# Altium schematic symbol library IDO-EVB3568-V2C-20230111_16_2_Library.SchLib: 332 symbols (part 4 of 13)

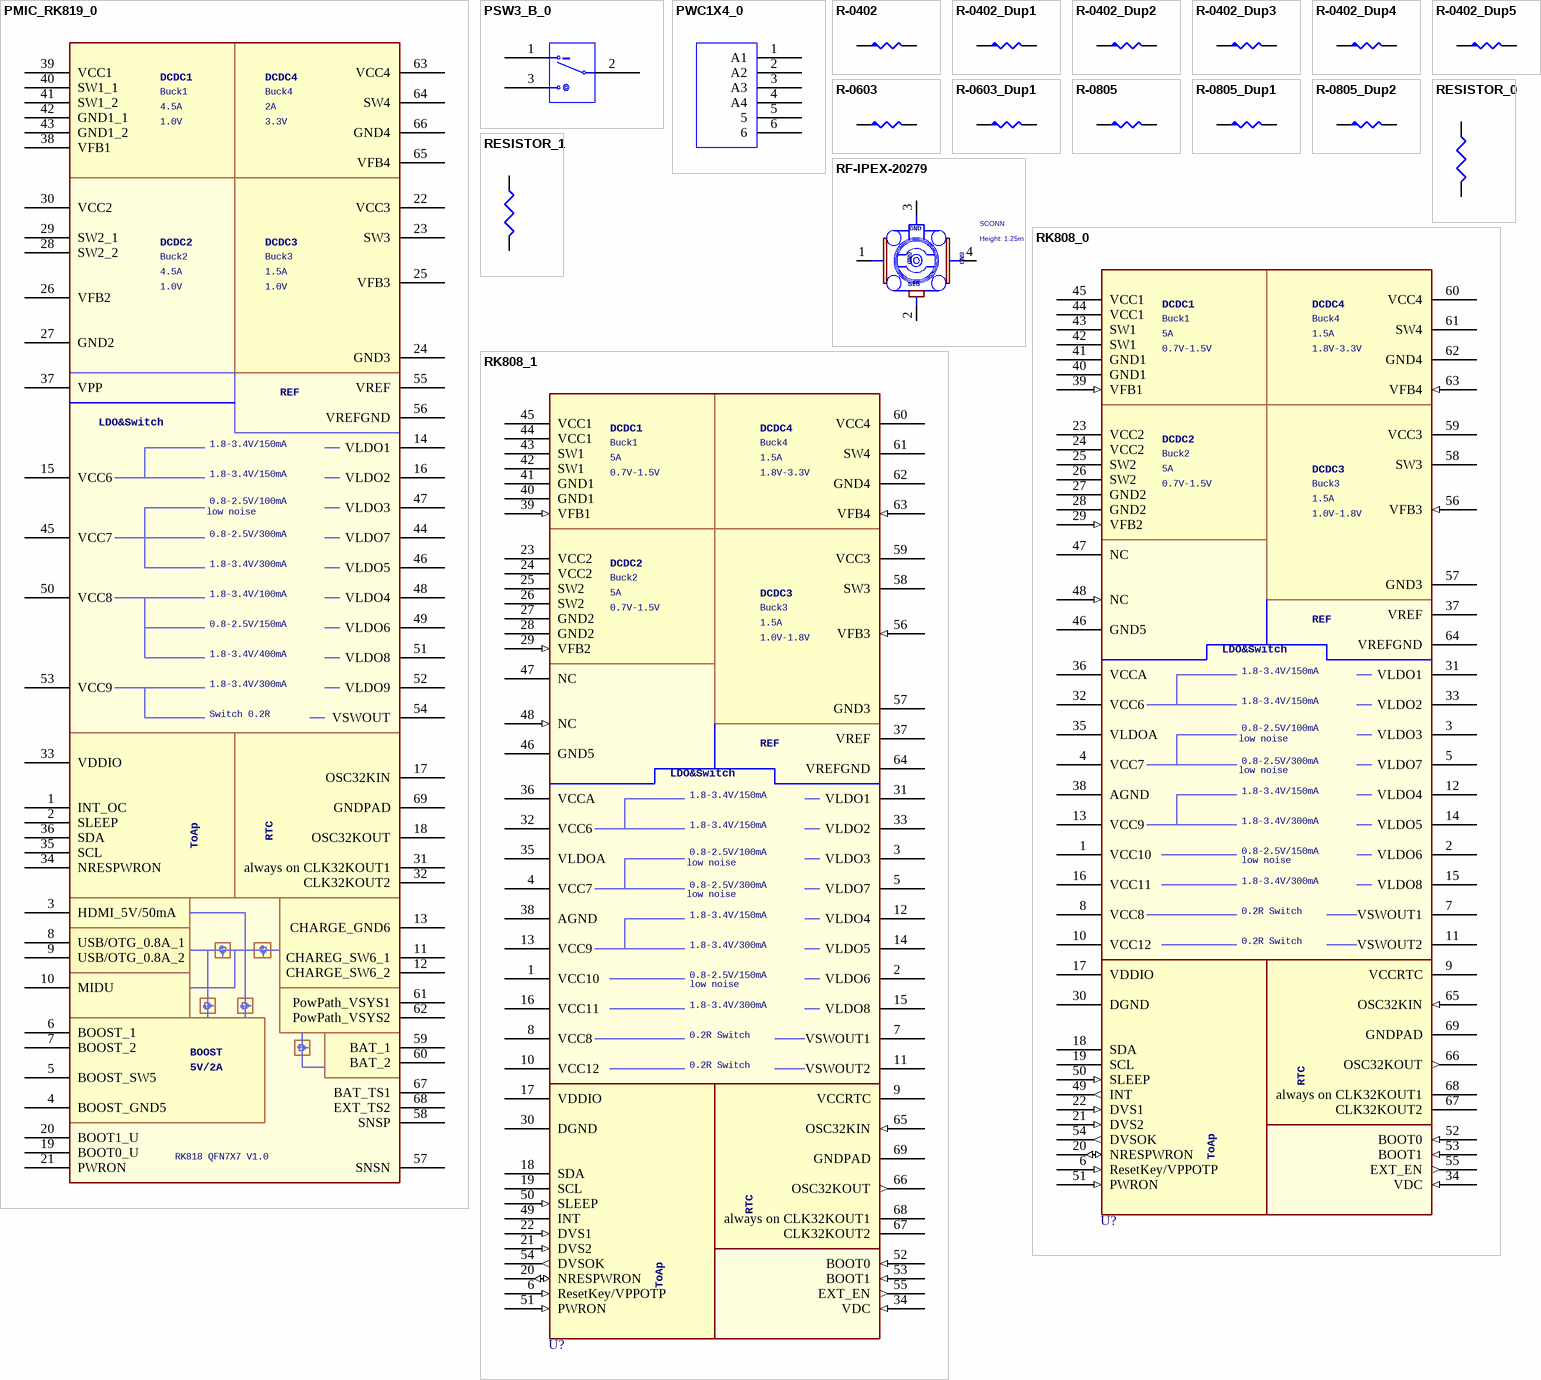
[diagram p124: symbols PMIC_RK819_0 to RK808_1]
## PWC1X4_0
designator J?, comment PWC1X4  (value not drawn)
PARTS: 1; DEVICE: HEAD1X4; LEVEL: STD; PKG_TYPE: 4; OriginalSymbolOrigin: (0,70)
pins: 1 A1, 2 A2, 3 A3, 4 A4, 5, 6

## R-0402
designator R?
pins: 1, 2

## R-0402_Dup1
designator R?
pins: 1, 2

## R-0402_Dup2
designator R?
pins: 1, 2

## R-0402_Dup3
designator R?
pins: 1, 2

## R-0402_Dup4
designator R?
pins: 1, 2

## R-0402_Dup5
designator R?
pins: 1, 2

## R-0603
designator R?
pins: 1, 2

## R-0603_Dup1
designator R?
pins: 1, 2

## R-0805
designator R?
pins: 1, 2

## R-0805_Dup1
designator R?
pins: 1, 2

## R-0805_Dup2
designator R?
pins: 1, 2

## RESISTOR_0
designator R?
pins: 1, 2

## RESISTOR_1
designator R?
pins: 1, 2

## RF-IPEX-20279
designator IPEX?  Material: SCONN  Height: 1.25mm
SMD micro Coaxial Connector Receptacle vertial; Pack_Type: MHF-20279
pins: 1 GND1, 2 SIG, 3 GND2, 4 GND3

## RK808_0
designator U?  (value not drawn)
pins: 1 VCC10 (power), 2 VLDO6 (power), 3 VLDO3 (power), 4 VCC7 (power), 5 VLDO7 (power), 6 ResetKey/VPPOTP (in), 7 VSWOUT1 (power), 8 VCC8 (power), 9 VCCRTC (power), 10 VCC12 (power), 11 VSWOUT2 (power), 12 VLDO4 (power), 13 VCC9 (power), 14 VLDO5 (power), 15 VLDO8 (power), 16 VCC11 (power), 17 VDDIO (power), 18 SDA (oc), 19 SCL (oc), 20 NRESPWRON (io), 21 DVS2 (in), 22 DVS1 (in), 23 VCC2 (power), 24 VCC2 (power), 25 SW2 (power), 26 SW2 (power), 27 GND2 (power), 28 GND2 (power), 29 VFB2 (in), 30 DGND (power), 31 VLDO1 (power), 32 VCC6 (power), 33 VLDO2 (power), 34 VDC (in), 35 VLDOA (power), 36 VCCA (power), 37 VREF (power), 38 AGND (power), 39 VFB1 (in), 40 GND1 (power), 41 GND1 (power), 42 SW1 (power), 43 SW1 (power), 44 VCC1 (power), 45 VCC1 (power), 46 GND5 (power), 47 NC (hiz), 48 NC (in), 49 INT (out), 50 SLEEP (in), 51 PWRON (in), 52 BOOT0 (in), 53 BOOT1 (in), 54 DVSOK (out), 55 EXT_EN (out), 56 VFB3 (in), 57 GND3 (power), 58 SW3 (power), 59 VCC3 (power), 60 VCC4 (power), 61 SW4 (power), 62 GND4 (power), 63 VFB4 (in), 64 VREFGND (power), 65 OSC32KIN (in), 66 OSC32KOUT (out), 67 CLK32KOUT2 (oc), 68 always on CLK32KOUT1 (oc), 69 GNDPAD (power)

## RK808_1
designator U?  (value not drawn)
pins: 1 VCC10 (power), 2 VLDO6 (power), 3 VLDO3 (power), 4 VCC7 (power), 5 VLDO7 (power), 6 ResetKey/VPPOTP (in), 7 VSWOUT1 (power), 8 VCC8 (power), 9 VCCRTC (power), 10 VCC12 (power), 11 VSWOUT2 (power), 12 VLDO4 (power), 13 VCC9 (power), 14 VLDO5 (power), 15 VLDO8 (power), 16 VCC11 (power), 17 VDDIO (power), 18 SDA (oc), 19 SCL (oc), 20 NRESPWRON (io), 21 DVS2 (in), 22 DVS1 (in), 23 VCC2 (power), 24 VCC2 (power), 25 SW2 (power), 26 SW2 (power), 27 GND2 (power), 28 GND2 (power), 29 VFB2 (in), 30 DGND (power), 31 VLDO1 (power), 32 VCC6 (power), 33 VLDO2 (power), 34 VDC (in), 35 VLDOA (power), 36 VCCA (power), 37 VREF (power), 38 AGND (power), 39 VFB1 (in), 40 GND1 (power), 41 GND1 (power), 42 SW1 (power), 43 SW1 (power), 44 VCC1 (power), 45 VCC1 (power), 46 GND5 (power), 47 NC (hiz), 48 NC (in), 49 INT, 50 SLEEP (in), 51 PWRON (in), 52 BOOT0 (in), 53 BOOT1 (in), 54 DVSOK (out), 55 EXT_EN (out), 56 VFB3 (in), 57 GND3 (power), 58 SW3 (power), 59 VCC3 (power), 60 VCC4 (power), 61 SW4 (power), 62 GND4 (power), 63 VFB4 (in), 64 VREFGND (power), 65 OSC32KIN (in), 66 OSC32KOUT (out), 67 CLK32KOUT2 (oc), 68 always on CLK32KOUT1 (oc), 69 GNDPAD (power)


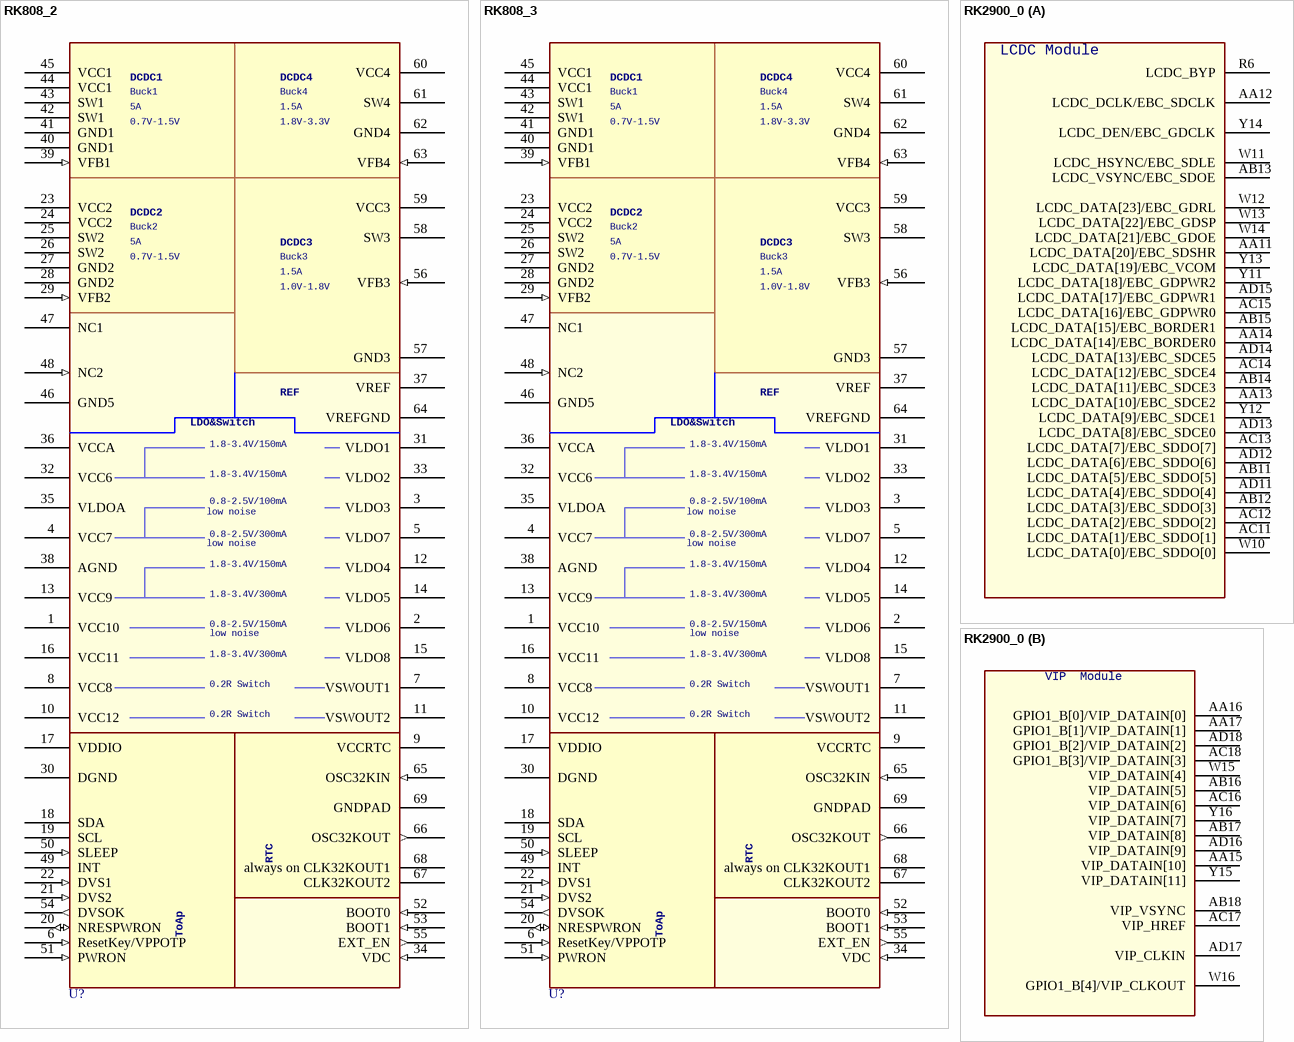
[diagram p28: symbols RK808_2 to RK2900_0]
## RK808_2
designator U?  (value not drawn)
pins: 1 VCC10 (power), 2 VLDO6 (power), 3 VLDO3 (power), 4 VCC7 (power), 5 VLDO7 (power), 6 ResetKey/VPPOTP (in), 7 VSWOUT1 (power), 8 VCC8 (power), 9 VCCRTC (power), 10 VCC12 (power), 11 VSWOUT2 (power), 12 VLDO4 (power), 13 VCC9 (power), 14 VLDO5 (power), 15 VLDO8 (power), 16 VCC11 (power), 17 VDDIO (power), 18 SDA (oc), 19 SCL (oc), 20 NRESPWRON (io), 21 DVS2 (in), 22 DVS1 (in), 23 VCC2 (power), 24 VCC2 (power), 25 SW2 (power), 26 SW2 (power), 27 GND2 (power), 28 GND2 (power), 29 VFB2 (in), 30 DGND (power), 31 VLDO1 (power), 32 VCC6 (power), 33 VLDO2 (power), 34 VDC (in), 35 VLDOA (power), 36 VCCA (power), 37 VREF (power), 38 AGND (power), 39 VFB1 (in), 40 GND1 (power), 41 GND1 (power), 42 SW1 (power), 43 SW1 (power), 44 VCC1 (power), 45 VCC1 (power), 46 GND5 (power), 47 NC1 (hiz), 48 NC2 (in), 49 INT, 50 SLEEP (in), 51 PWRON (in), 52 BOOT0 (in), 53 BOOT1 (in), 54 DVSOK (out), 55 EXT_EN (out), 56 VFB3 (in), 57 GND3 (power), 58 SW3 (power), 59 VCC3 (power), 60 VCC4 (power), 61 SW4 (power), 62 GND4 (power), 63 VFB4 (in), 64 VREFGND (power), 65 OSC32KIN (in), 66 OSC32KOUT (out), 67 CLK32KOUT2 (oc), 68 always on CLK32KOUT1 (oc), 69 GNDPAD (power)

## RK808_3
designator U?  (value not drawn)
pins: 1 VCC10 (power), 2 VLDO6 (power), 3 VLDO3 (power), 4 VCC7 (power), 5 VLDO7 (power), 6 ResetKey/VPPOTP (in), 7 VSWOUT1 (power), 8 VCC8 (power), 9 VCCRTC (power), 10 VCC12 (power), 11 VSWOUT2 (power), 12 VLDO4 (power), 13 VCC9 (power), 14 VLDO5 (power), 15 VLDO8 (power), 16 VCC11 (power), 17 VDDIO (power), 18 SDA (oc), 19 SCL (oc), 20 NRESPWRON (io), 21 DVS2 (in), 22 DVS1 (in), 23 VCC2 (power), 24 VCC2 (power), 25 SW2 (power), 26 SW2 (power), 27 GND2 (power), 28 GND2 (power), 29 VFB2 (in), 30 DGND (power), 31 VLDO1 (power), 32 VCC6 (power), 33 VLDO2 (power), 34 VDC (in), 35 VLDOA (power), 36 VCCA (power), 37 VREF (power), 38 AGND (power), 39 VFB1 (in), 40 GND1 (power), 41 GND1 (power), 42 SW1 (power), 43 SW1 (power), 44 VCC1 (power), 45 VCC1 (power), 46 GND5 (power), 47 NC1 (hiz), 48 NC2 (in), 49 INT, 50 SLEEP (in), 51 PWRON (in), 52 BOOT0 (in), 53 BOOT1 (in), 54 DVSOK (out), 55 EXT_EN (out), 56 VFB3 (in), 57 GND3 (power), 58 SW3 (power), 59 VCC3 (power), 60 VCC4 (power), 61 SW4 (power), 62 GND4 (power), 63 VFB4 (in), 64 VREFGND (power), 65 OSC32KIN (in), 66 OSC32KOUT (out), 67 CLK32KOUT2 (oc), 68 always on CLK32KOUT1 (oc), 69 GNDPAD (power)




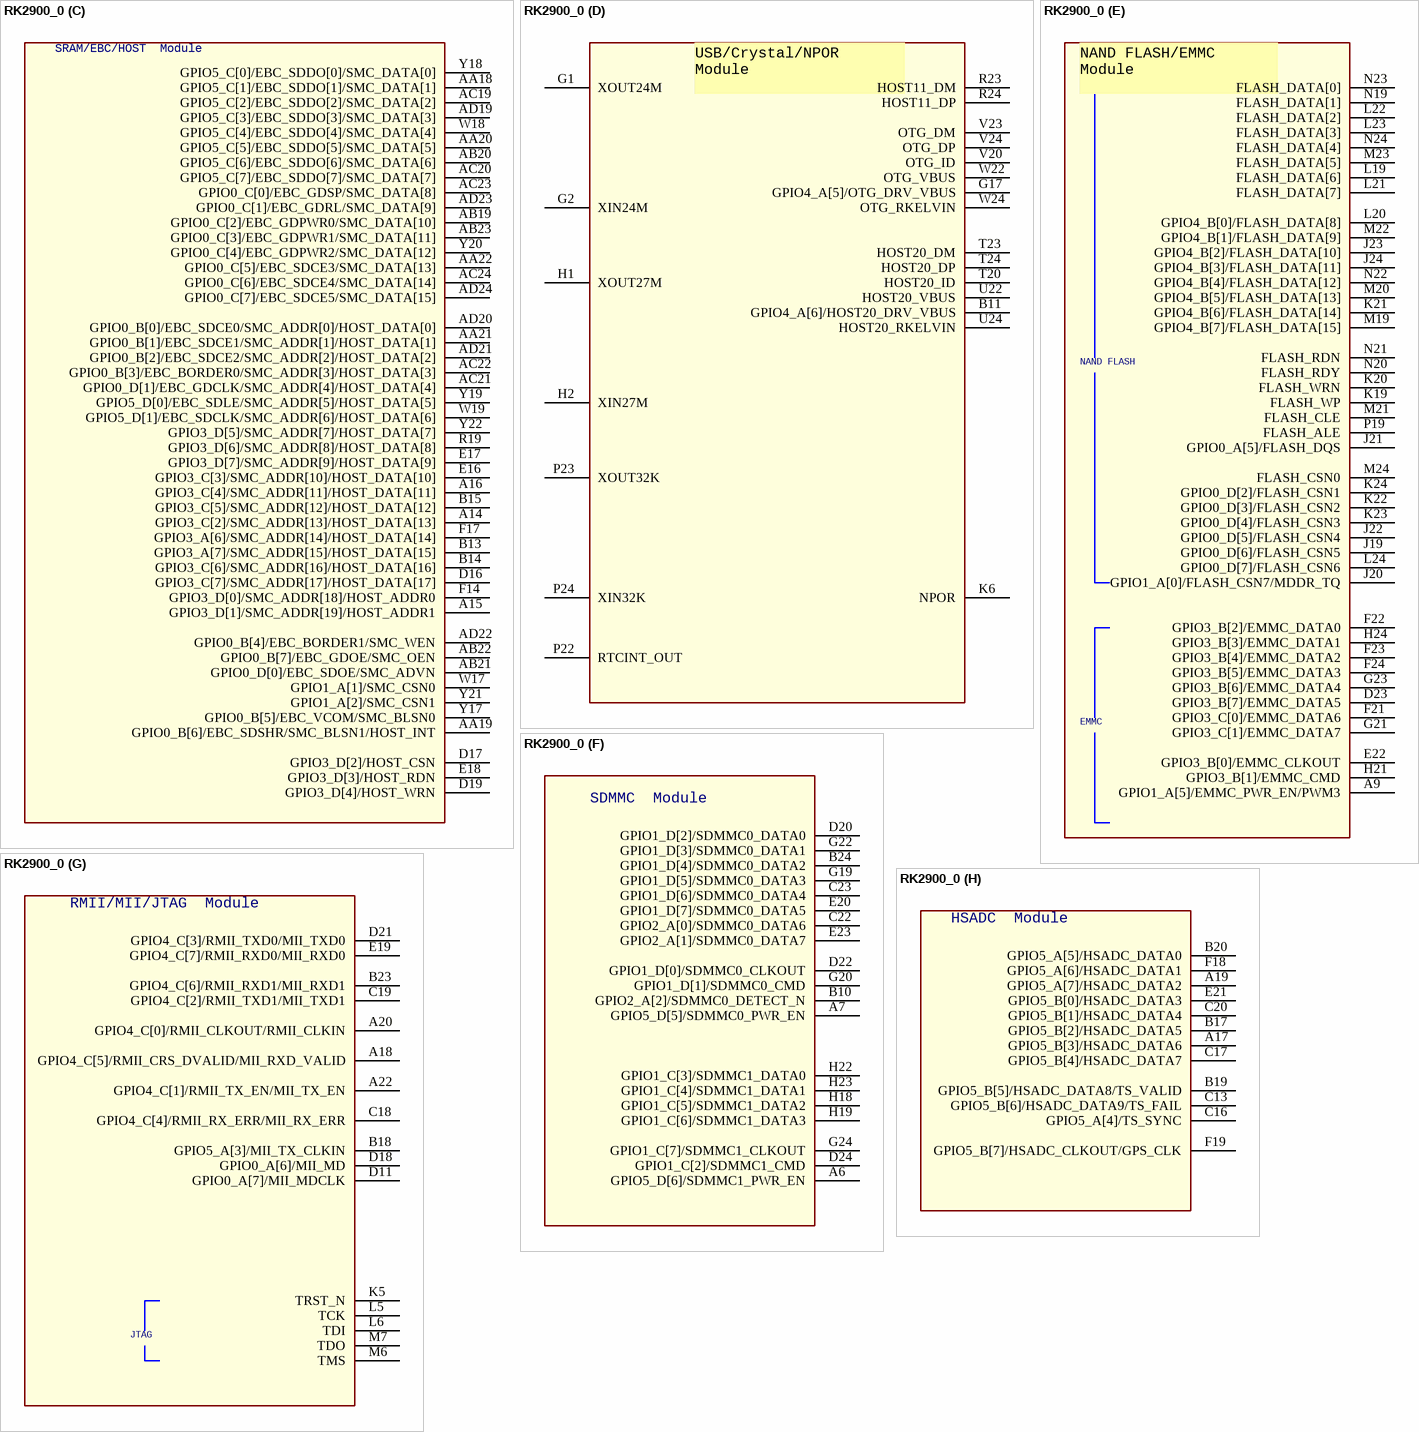
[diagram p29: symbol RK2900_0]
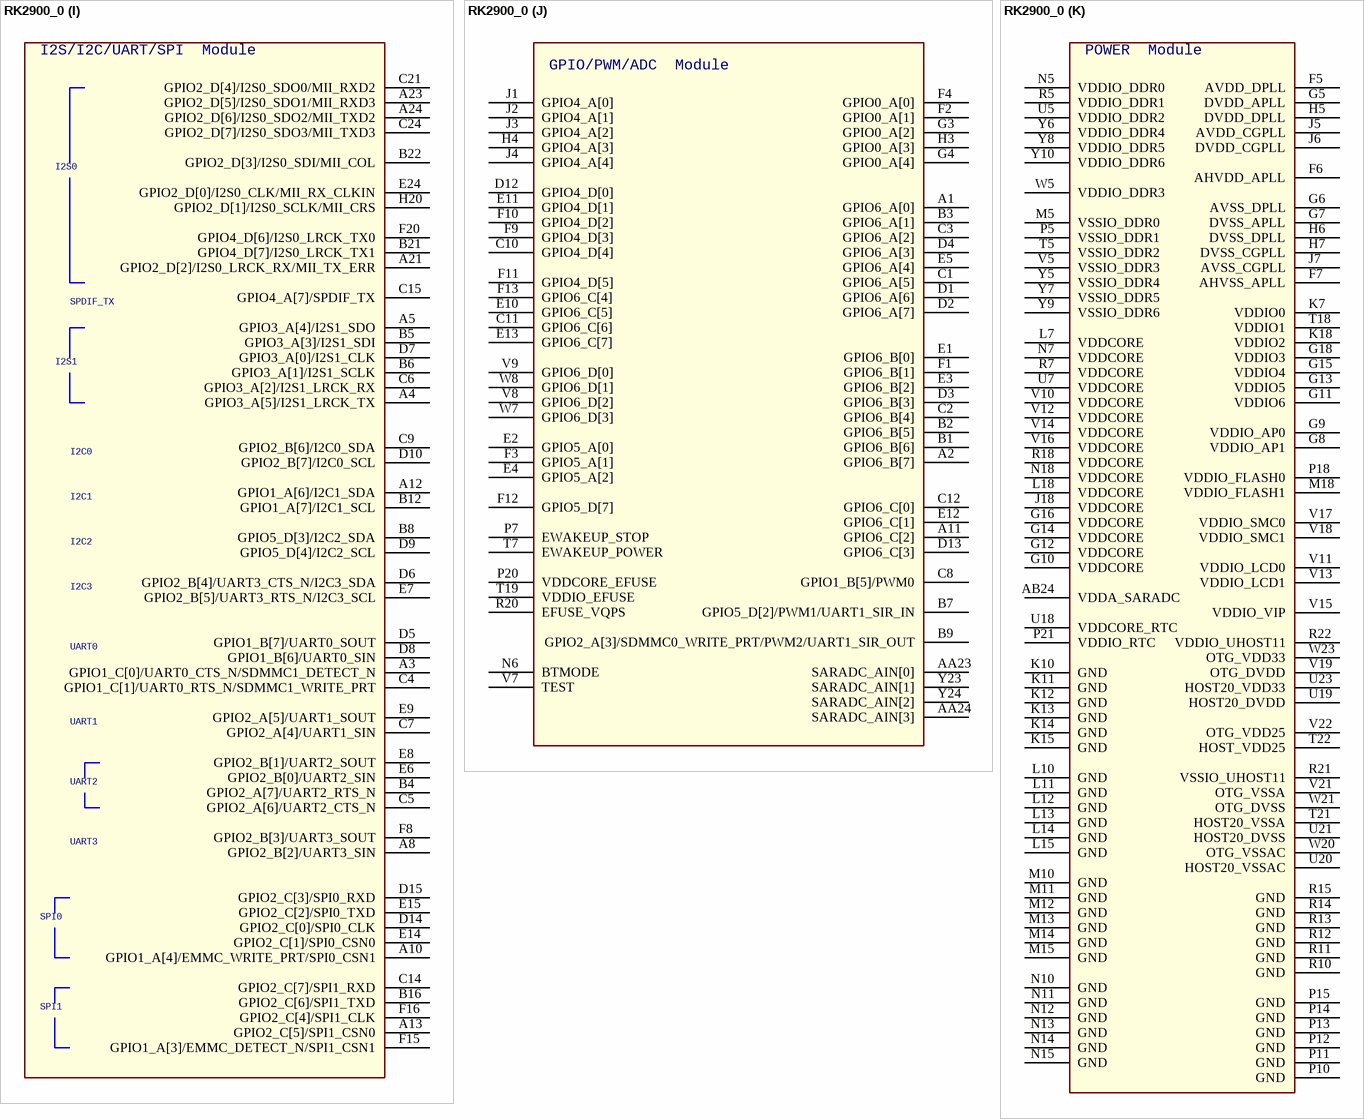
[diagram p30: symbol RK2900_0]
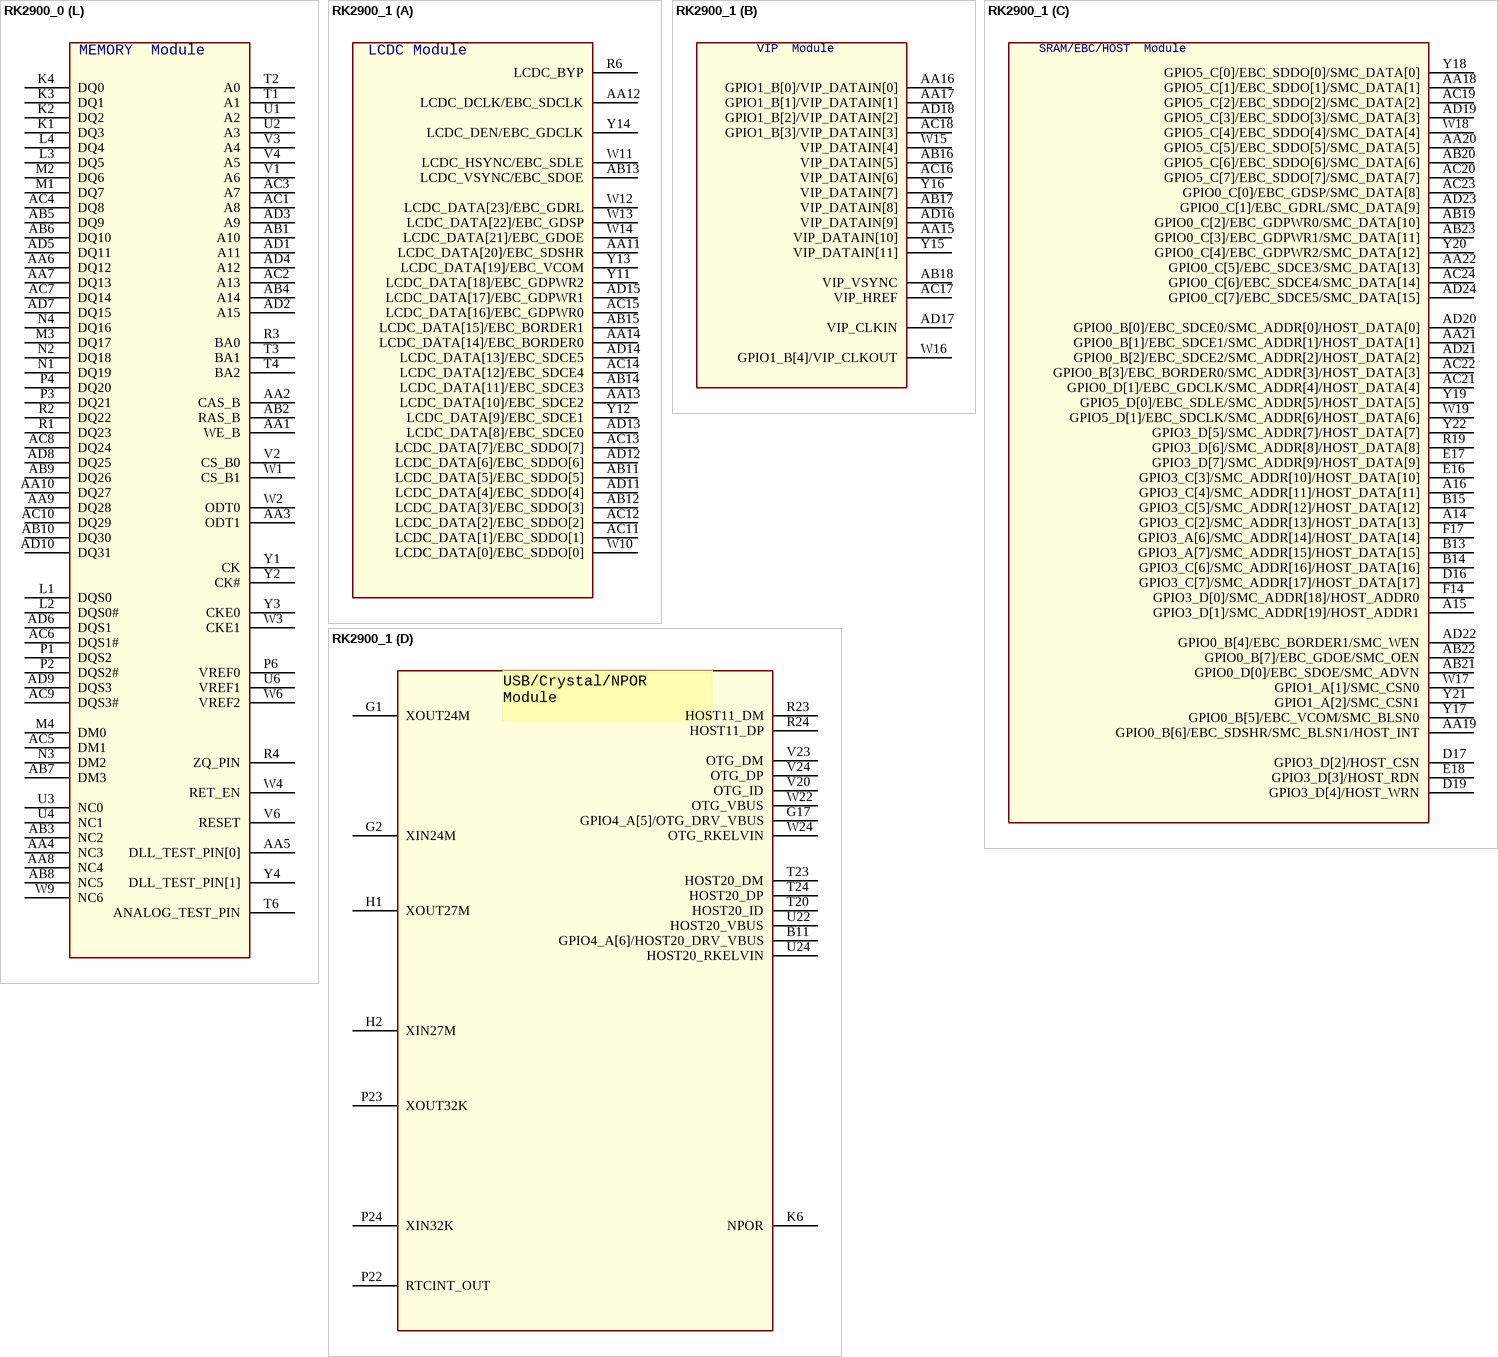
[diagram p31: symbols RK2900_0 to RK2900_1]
## RK2900_0
designator U?
footprint BGA512
part A pins: AA11 LCDC_DATA[20]/EBC_SDSHR, AA12 LCDC_DCLK/EBC_SDCLK, AA13 LCDC_DATA[10]/EBC_SDCE2, AA14 LCDC_DATA[14]/EBC_BORDER0, AB11 LCDC_DATA[5]/EBC_SDDO[5], AB12 LCDC_DATA[3]/EBC_SDDO[3], AB13 LCDC_VSYNC/EBC_SDOE, AB14 LCDC_DATA[11]/EBC_SDCE3, AB15 LCDC_DATA[15]/EBC_BORDER1, AC11 LCDC_DATA[1]/EBC_SDDO[1], AC12 LCDC_DATA[2]/EBC_SDDO[2], AC13 LCDC_DATA[7]/EBC_SDDO[7], AC14 LCDC_DATA[12]/EBC_SDCE4, AC15 LCDC_DATA[16]/EBC_GDPWR0, AD11 LCDC_DATA[4]/EBC_SDDO[4], AD12 LCDC_DATA[6]/EBC_SDDO[6], AD13 LCDC_DATA[8]/EBC_SDCE0, AD14 LCDC_DATA[13]/EBC_SDCE5, AD15 LCDC_DATA[17]/EBC_GDPWR1, R6 LCDC_BYP, W10 LCDC_DATA[0]/EBC_SDDO[0], W11 LCDC_HSYNC/EBC_SDLE, W12 LCDC_DATA[23]/EBC_GDRL, W13 LCDC_DATA[22]/EBC_GDSP, W14 LCDC_DATA[21]/EBC_GDOE, Y11 LCDC_DATA[18]/EBC_GDPWR2, Y12 LCDC_DATA[9]/EBC_SDCE1, Y13 LCDC_DATA[19]/EBC_VCOM, Y14 LCDC_DEN/EBC_GDCLK
part B pins: AA15 VIP_DATAIN[10], AA16 GPIO1_B[0]/VIP_DATAIN[0], AA17 GPIO1_B[1]/VIP_DATAIN[1], AB16 VIP_DATAIN[5], AB17 VIP_DATAIN[8], AB18 VIP_VSYNC, AC16 VIP_DATAIN[6], AC17 VIP_HREF, AC18 GPIO1_B[3]/VIP_DATAIN[3], AD16 VIP_DATAIN[9], AD17 VIP_CLKIN, AD18 GPIO1_B[2]/VIP_DATAIN[2], W15 VIP_DATAIN[4], W16 GPIO1_B[4]/VIP_CLKOUT, Y15 VIP_DATAIN[11], Y16 VIP_DATAIN[7]
part C pins: A14 GPIO3_C[2]/SMC_ADDR[13]/HOST_DATA[13], A15 GPIO3_D[1]/SMC_ADDR[19]/HOST_ADDR1, A16 GPIO3_C[4]/SMC_ADDR[11]/HOST_DATA[11], AA18 GPIO5_C[1]/EBC_SDDO[1]/SMC_DATA[1], AA19 GPIO0_B[6]/EBC_SDSHR/SMC_BLSN1/HOST_INT, AA20 GPIO5_C[5]/EBC_SDDO[5]/SMC_DATA[5], AA21 GPIO0_B[1]/EBC_SDCE1/SMC_ADDR[1]/HOST_DATA[1], AA22 GPIO0_C[5]/EBC_SDCE3/SMC_DATA[13], AB19 GPIO0_C[2]/EBC_GDPWR0/SMC_DATA[10], AB20 GPIO5_C[6]/EBC_SDDO[6]/SMC_DATA[6], AB21 GPIO0_D[0]/EBC_SDOE/SMC_ADVN, AB22 GPIO0_B[7]/EBC_GDOE/SMC_OEN, AB23 GPIO0_C[3]/EBC_GDPWR1/SMC_DATA[11], AC19 GPIO5_C[2]/EBC_SDDO[2]/SMC_DATA[2], AC20 GPIO5_C[7]/EBC_SDDO[7]/SMC_DATA[7], AC21 GPIO0_D[1]/EBC_GDCLK/SMC_ADDR[4]/HOST_DATA[4], AC22 GPIO0_B[3]/EBC_BORDER0/SMC_ADDR[3]/HOST_DATA[3], AC23 GPIO0_C[0]/EBC_GDSP/SMC_DATA[8], AC24 GPIO0_C[6]/EBC_SDCE4/SMC_DATA[14], AD19 GPIO5_C[3]/EBC_SDDO[3]/SMC_DATA[3], AD20 GPIO0_B[0]/EBC_SDCE0/SMC_ADDR[0]/HOST_DATA[0], AD21 GPIO0_B[2]/EBC_SDCE2/SMC_ADDR[2]/HOST_DATA[2], AD22 GPIO0_B[4]/EBC_BORDER1/SMC_WEN, AD23 GPIO0_C[1]/EBC_GDRL/SMC_DATA[9], AD24 GPIO0_C[7]/EBC_SDCE5/SMC_DATA[15], B13 GPIO3_A[7]/SMC_ADDR[15]/HOST_DATA[15], B14 GPIO3_C[6]/SMC_ADDR[16]/HOST_DATA[16], B15 GPIO3_C[5]/SMC_ADDR[12]/HOST_DATA[12], D16 GPIO3_C[7]/SMC_ADDR[17]/HOST_DATA[17], D17 GPIO3_D[2]/HOST_CSN, D19 GPIO3_D[4]/HOST_WRN, E16 GPIO3_C[3]/SMC_ADDR[10]/HOST_DATA[10], E17 GPIO3_D[7]/SMC_ADDR[9]/HOST_DATA[9], E18 GPIO3_D[3]/HOST_RDN, F14 GPIO3_D[0]/SMC_ADDR[18]/HOST_ADDR0, F17 GPIO3_A[6]/SMC_ADDR[14]/HOST_DATA[14], R19 GPIO3_D[6]/SMC_ADDR[8]/HOST_DATA[8], W17 GPIO1_A[1]/SMC_CSN0, W18 GPIO5_C[4]/EBC_SDDO[4]/SMC_DATA[4], W19 GPIO5_D[1]/EBC_SDCLK/SMC_ADDR[6]/HOST_DATA[6], Y17 GPIO0_B[5]/EBC_VCOM/SMC_BLSN0, Y18 GPIO5_C[0]/EBC_SDDO[0]/SMC_DATA[0], Y19 GPIO5_D[0]/EBC_SDLE/SMC_ADDR[5]/HOST_DATA[5], Y20 GPIO0_C[4]/EBC_GDPWR2/SMC_DATA[12], Y21 GPIO1_A[2]/SMC_CSN1, Y22 GPIO3_D[5]/SMC_ADDR[7]/HOST_DATA[7]
part D pins: B11 GPIO4_A[6]/HOST20_DRV_VBUS, G1 XOUT24M, G2 XIN24M, G17 GPIO4_A[5]/OTG_DRV_VBUS, H1 XOUT27M, H2 XIN27M, K6 NPOR, P22 RTCINT_OUT, P23 XOUT32K, P24 XIN32K, R23 HOST11_DM, R24 HOST11_DP, T20 HOST20_ID, T23 HOST20_DM, T24 HOST20_DP, U22 HOST20_VBUS, U24 HOST20_RKELVIN, V20 OTG_ID, V23 OTG_DM, V24 OTG_DP, W22 OTG_VBUS, W24 OTG_RKELVIN
part E pins: A9 GPIO1_A[5]/EMMC_PWR_EN/PWM3, D23 GPIO3_B[7]/EMMC_DATA5, E22 GPIO3_B[0]/EMMC_CLKOUT, F21 GPIO3_C[0]/EMMC_DATA6, F22 GPIO3_B[2]/EMMC_DATA0, F23 GPIO3_B[4]/EMMC_DATA2, F24 GPIO3_B[5]/EMMC_DATA3, G21 GPIO3_C[1]/EMMC_DATA7, G23 GPIO3_B[6]/EMMC_DATA4, H21 GPIO3_B[1]/EMMC_CMD, H24 GPIO3_B[3]/EMMC_DATA1, J19 GPIO0_D[6]/FLASH_CSN5, J20 GPIO1_A[0]/FLASH_CSN7/MDDR_TQ, J21 GPIO0_A[5]/FLASH_DQS, J22 GPIO0_D[5]/FLASH_CSN4, J23 GPIO4_B[2]/FLASH_DATA[10], J24 GPIO4_B[3]/FLASH_DATA[11], K19 FLASH_WP, K20 FLASH_WRN, K21 GPIO4_B[6]/FLASH_DATA[14], K22 GPIO0_D[3]/FLASH_CSN2, K23 GPIO0_D[4]/FLASH_CSN3, K24 GPIO0_D[2]/FLASH_CSN1, L19 FLASH_DATA[6], L20 GPIO4_B[0]/FLASH_DATA[8], L21 FLASH_DATA[7], L22 FLASH_DATA[2], L23 FLASH_DATA[3], L24 GPIO0_D[7]/FLASH_CSN6, M19 GPIO4_B[7]/FLASH_DATA[15], M20 GPIO4_B[5]/FLASH_DATA[13], M21 FLASH_CLE, M22 GPIO4_B[1]/FLASH_DATA[9], M23 FLASH_DATA[5], M24 FLASH_CSN0, N19 FLASH_DATA[1], N20 FLASH_RDY, N21 FLASH_RDN, N22 GPIO4_B[4]/FLASH_DATA[12], N23 FLASH_DATA[0], N24 FLASH_DATA[4], P19 FLASH_ALE
part F pins: A6 GPIO5_D[6]/SDMMC1_PWR_EN, A7 GPIO5_D[5]/SDMMC0_PWR_EN, B10 GPIO2_A[2]/SDMMC0_DETECT_N, B24 GPIO1_D[4]/SDMMC0_DATA2, C22 GPIO2_A[0]/SDMMC0_DATA6, C23 GPIO1_D[6]/SDMMC0_DATA4, D20 GPIO1_D[2]/SDMMC0_DATA0, D22 GPIO1_D[0]/SDMMC0_CLKOUT, D24 GPIO1_C[2]/SDMMC1_CMD, E20 GPIO1_D[7]/SDMMC0_DATA5, E23 GPIO2_A[1]/SDMMC0_DATA7, G19 GPIO1_D[5]/SDMMC0_DATA3, G20 GPIO1_D[1]/SDMMC0_CMD, G22 GPIO1_D[3]/SDMMC0_DATA1, G24 GPIO1_C[7]/SDMMC1_CLKOUT, H18 GPIO1_C[5]/SDMMC1_DATA2, H19 GPIO1_C[6]/SDMMC1_DATA3, H22 GPIO1_C[3]/SDMMC1_DATA0, H23 GPIO1_C[4]/SDMMC1_DATA1
part G pins: A18 GPIO4_C[5]/RMII_CRS_DVALID/MII_RXD_VALID, A20 GPIO4_C[0]/RMII_CLKOUT/RMII_CLKIN, A22 GPIO4_C[1]/RMII_TX_EN/MII_TX_EN, B18 GPIO5_A[3]/MII_TX_CLKIN, B23 GPIO4_C[6]/RMII_RXD1/MII_RXD1, C18 GPIO4_C[4]/RMII_RX_ERR/MII_RX_ERR, C19 GPIO4_C[2]/RMII_TXD1/MII_TXD1, D11 GPIO0_A[7]/MII_MDCLK, D18 GPIO0_A[6]/MII_MD, D21 GPIO4_C[3]/RMII_TXD0/MII_TXD0, E19 GPIO4_C[7]/RMII_RXD0/MII_RXD0, K5 TRST_N, L5 TCK, L6 TDI, M6 TMS, M7 TDO
part H pins: A17 GPIO5_B[3]/HSADC_DATA6, A19 GPIO5_A[7]/HSADC_DATA2, B17 GPIO5_B[2]/HSADC_DATA5, B19 GPIO5_B[5]/HSADC_DATA8/TS_VALID, B20 GPIO5_A[5]/HSADC_DATA0, C13 GPIO5_B[6]/HSADC_DATA9/TS_FAIL, C16 GPIO5_A[4]/TS_SYNC, C17 GPIO5_B[4]/HSADC_DATA7, C20 GPIO5_B[1]/HSADC_DATA4, E21 GPIO5_B[0]/HSADC_DATA3, F18 GPIO5_A[6]/HSADC_DATA1, F19 GPIO5_B[7]/HSADC_CLKOUT/GPS_CLK
part I pins: A3 GPIO1_C[0]/UART0_CTS_N/SDMMC1_DETECT_N, A4 GPIO3_A[5]/I2S1_LRCK_TX, A5 GPIO3_A[4]/I2S1_SDO, A8 GPIO2_B[2]/UART3_SIN, A10 GPIO1_A[4]/EMMC_WRITE_PRT/SPI0_CSN1, A12 GPIO1_A[6]/I2C1_SDA, A13 GPIO2_C[5]/SPI1_CSN0, A21 GPIO2_D[2]/I2S0_LRCK_RX/MII_TX_ERR, A23 GPIO2_D[5]/I2S0_SDO1/MII_RXD3, A24 GPIO2_D[6]/I2S0_SDO2/MII_TXD2, B4 GPIO2_A[7]/UART2_RTS_N, B5 GPIO3_A[3]/I2S1_SDI, B6 GPIO3_A[1]/I2S1_SCLK, B8 GPIO5_D[3]/I2C2_SDA, B12 GPIO1_A[7]/I2C1_SCL, B16 GPIO2_C[6]/SPI1_TXD, B21 GPIO4_D[7]/I2S0_LRCK_TX1, B22 GPIO2_D[3]/I2S0_SDI/MII_COL, C4 GPIO1_C[1]/UART0_RTS_N/SDMMC1_WRITE_PRT, C5 GPIO2_A[6]/UART2_CTS_N, C6 GPIO3_A[2]/I2S1_LRCK_RX, C7 GPIO2_A[4]/UART1_SIN, C9 GPIO2_B[6]/I2C0_SDA, C14 GPIO2_C[7]/SPI1_RXD, C15 GPIO4_A[7]/SPDIF_TX, C21 GPIO2_D[4]/I2S0_SDO0/MII_RXD2, C24 GPIO2_D[7]/I2S0_SDO3/MII_TXD3, D5 GPIO1_B[7]/UART0_SOUT, D6 GPIO2_B[4]/UART3_CTS_N/I2C3_SDA, D7 GPIO3_A[0]/I2S1_CLK, D8 GPIO1_B[6]/UART0_SIN, D9 GPIO5_D[4]/I2C2_SCL, D10 GPIO2_B[7]/I2C0_SCL, D14 GPIO2_C[0]/SPI0_CLK, D15 GPIO2_C[3]/SPI0_RXD, E6 GPIO2_B[0]/UART2_SIN, E7 GPIO2_B[5]/UART3_RTS_N/I2C3_SCL, E8 GPIO2_B[1]/UART2_SOUT, E9 GPIO2_A[5]/UART1_SOUT, E14 GPIO2_C[1]/SPI0_CSN0, E15 GPIO2_C[2]/SPI0_TXD, E24 GPIO2_D[0]/I2S0_CLK/MII_RX_CLKIN, F8 GPIO2_B[3]/UART3_SOUT, F15 GPIO1_A[3]/EMMC_DETECT_N/SPI1_CSN1, F16 GPIO2_C[4]/SPI1_CLK, F20 GPIO4_D[6]/I2S0_LRCK_TX0, H20 GPIO2_D[1]/I2S0_SCLK/MII_CRS
part J pins: A1 GPIO6_A[0], A2 GPIO6_B[7], A11 GPIO6_C[2], AA23 SARADC_AIN[0], AA24 SARADC_AIN[3], B1 GPIO6_B[6], B2 GPIO6_B[5], B3 GPIO6_A[1], B7 GPIO5_D[2]/PWM1/UART1_SIR_IN, B9 GPIO2_A[3]/SDMMC0_WRITE_PRT/PWM2/UART1_SIR_OUT, C1 GPIO6_A[5], C2 GPIO6_B[4], C3 GPIO6_A[2], C8 GPIO1_B[5]/PWM0, C10 GPIO4_D[4], C11 GPIO6_C[6], C12 GPIO6_C[0], D1 GPIO6_A[6], D2 GPIO6_A[7], D3 GPIO6_B[3], D4 GPIO6_A[3], D12 GPIO4_D[0], D13 GPIO6_C[3], E1 GPIO6_B[0], E2 GPIO5_A[0], E3 GPIO6_B[2], E4 GPIO5_A[2], E5 GPIO6_A[4], E10 GPIO6_C[5], E11 GPIO4_D[1], E12 GPIO6_C[1], E13 GPIO6_C[7], F1 GPIO6_B[1], F2 GPIO0_A[1], F3 GPIO5_A[1], F4 GPIO0_A[0], F9 GPIO4_D[3], F10 GPIO4_D[2], F11 GPIO4_D[5], F12 GPIO5_D[7], F13 GPIO6_C[4], G3 GPIO0_A[2], G4 GPIO0_A[4], H3 GPIO0_A[3], H4 GPIO4_A[3], J1 GPIO4_A[0], J2 GPIO4_A[1], J3 GPIO4_A[2], J4 GPIO4_A[4], N6 BTMODE, P7 EWAKEUP_STOP, P20 VDDCORE_EFUSE, R20 EFUSE_VQPS, T7 EWAKEUP_POWER, T19 VDDIO_EFUSE, V7 TEST, V8 GPIO6_D[2], V9 GPIO6_D[0], W7 GPIO6_D[3], W8 GPIO6_D[1], Y23 SARADC_AIN[1], Y24 SARADC_AIN[2]
part K pins: AB24 VDDA_SARADC, F5 AVDD_DPLL, F6 AHVDD_APLL, F7 AHVSS_APLL, G5 DVDD_APLL, G6 AVSS_DPLL, G7 DVSS_APLL, G8 VDDIO_AP1, G9 VDDIO_AP0, G10 VDDCORE, G11 VDDIO6, G12 VDDCORE, G13 VDDIO5, G14 VDDCORE, G15 VDDIO4, G16 VDDCORE, G18 VDDIO3, H5 DVDD_DPLL, H6 DVSS_DPLL, H7 DVSS_CGPLL, J5 AVDD_CGPLL, J6 DVDD_CGPLL, J7 AVSS_CGPLL, J18 VDDCORE, K7 VDDIO0, K10 GND, K11 GND, K12 GND, K13 GND, K14 GND, K15 GND, K18 VDDIO2, L7 VDDCORE, L10 GND, L11 GND, L12 GND, L13 GND, L14 GND, L15 GND, L18 VDDCORE, M5 VSSIO_DDR0, M10 GND, M11 GND, M12 GND, M13 GND, M14 GND, M15 GND, M18 VDDIO_FLASH1, N5 VDDIO_DDR0, N7 VDDCORE, N10 GND, N11 GND, N12 GND, N13 GND, N14 GND, N15 GND, N18 VDDCORE, P5 VSSIO_DDR1, P10 GND, P11 GND, P12 GND, P13 GND, P14 GND, P15 GND, P18 VDDIO_FLASH0, P21 VDDIO_RTC, R5 VDDIO_DDR1, R7 VDDCORE, R10 GND, R11 GND, R12 GND, R13 GND, R14 GND, R15 GND, R18 VDDCORE, R21 VSSIO_UHOST11, R22 VDDIO_UHOST11, T5 VSSIO_DDR2, T18 VDDIO1, T21 HOST20_VSSA, T22 HOST_VDD25, U5 VDDIO_DDR2, U7 VDDCORE, U18 VDDCORE_RTC, U19 HOST20_DVDD, U20 HOST20_VSSAC, U21 HOST20_DVSS, U23 HOST20_VDD33, V5 VSSIO_DDR3, V10 VDDCORE, V11 VDDIO_LCD0, V12 VDDCORE, V13 VDDIO_LCD1, V14 VDDCORE, V15 VDDIO_VIP, V16 VDDCORE, V17 VDDIO_SMC0, V18 VDDIO_SMC1, V19 OTG_DVDD, V21 OTG_VSSA, V22 OTG_VDD25, W5 VDDIO_DDR3, W20 OTG_VSSAC, W21 OTG_DVSS, W23 OTG_VDD33, Y5 VSSIO_DDR4, Y6 VDDIO_DDR4, Y7 VSSIO_DDR5, Y8 VDDIO_DDR5, Y9 VSSIO_DDR6, Y10 VDDIO_DDR6
part L pins: AA1 WE_B, AA2 CAS_B, AA3 ODT1, AA4 NC3, AA5 DLL_TEST_PIN[0], AA6 DQ12, AA7 DQ13, AA8 NC4, AA9 DQ28, AA10 DQ27, AB1 A10, AB2 RAS_B, AB3 NC2, AB4 A14, AB5 DQ9, AB6 DQ10, AB7 DM3, AB8 NC5, AB9 DQ26, AB10 DQ30, AC1 A8, AC2 A13, AC3 A7, AC4 DQ8, AC5 DM1, AC6 DQS1#, AC7 DQ14, AC8 DQ24, AC9 DQS3#, AC10 DQ29, AD1 A11, AD2 A15, AD3 A9, AD4 A12, AD5 DQ11, AD6 DQS1, AD7 DQ15, AD8 DQ25, AD9 DQS3, AD10 DQ31, K1 DQ3, K2 DQ2, K3 DQ1, K4 DQ0, L1 DQS0, L2 DQS0#, L3 DQ5, L4 DQ4, M1 DQ7, M2 DQ6, M3 DQ17, M4 DM0, N1 DQ19, N2 DQ18, N3 DM2, N4 DQ16, P1 DQS2, P2 DQS2#, P3 DQ21, P4 DQ20, P6 VREF0, R1 DQ23, R2 DQ22, R3 BA0, R4 ZQ_PIN, T1 A1, T2 A0, T3 BA1, T4 BA2, T6 ANALOG_TEST_PIN, U1 A2, U2 A3, U3 NC0, U4 NC1, U6 VREF1, V1 A6, V2 CS_B0, V3 A4, V4 A5, V6 RESET, W1 CS_B1, W2 ODT0, W3 CKE1, W4 RET_EN, W6 VREF2, W9 NC6, Y1 CK, Y2 CK#, Y3 CKE0, Y4 DLL_TEST_PIN[1]




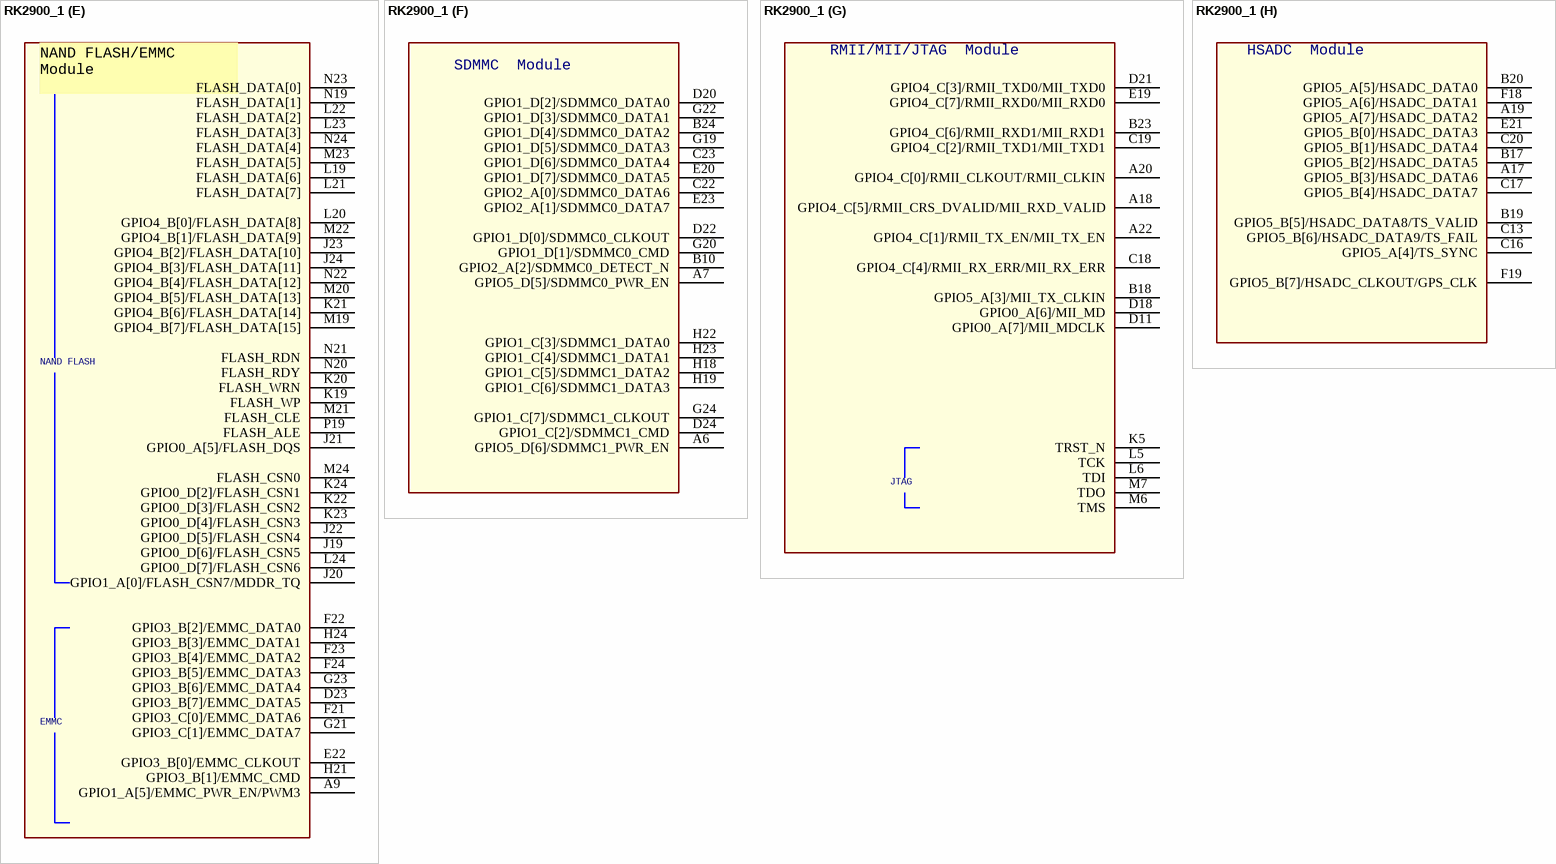
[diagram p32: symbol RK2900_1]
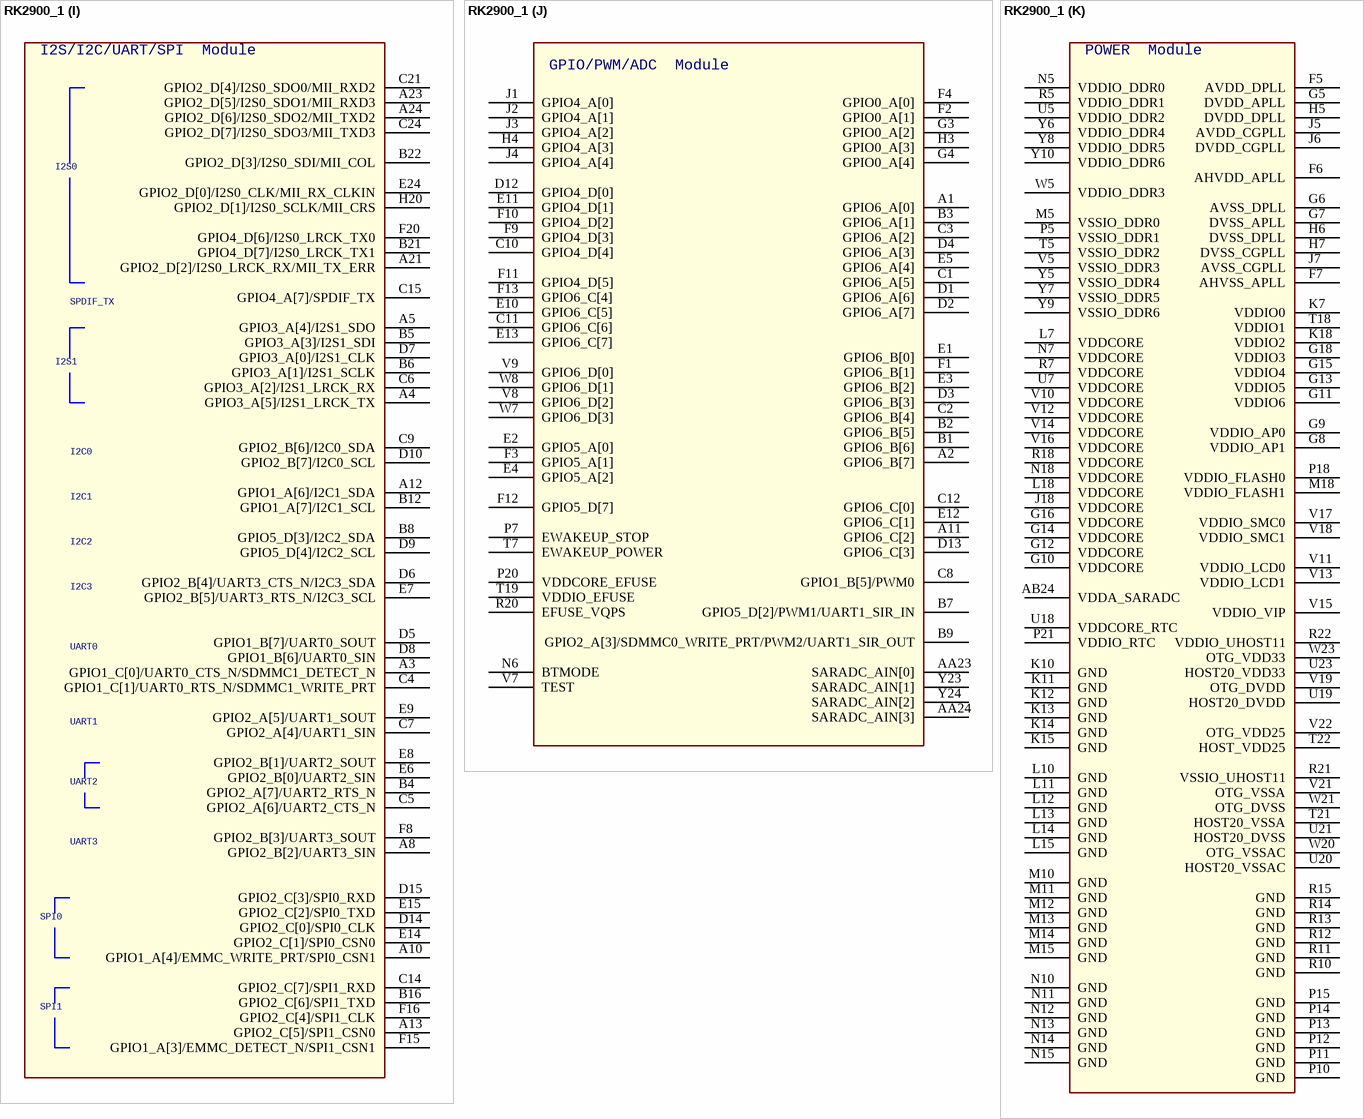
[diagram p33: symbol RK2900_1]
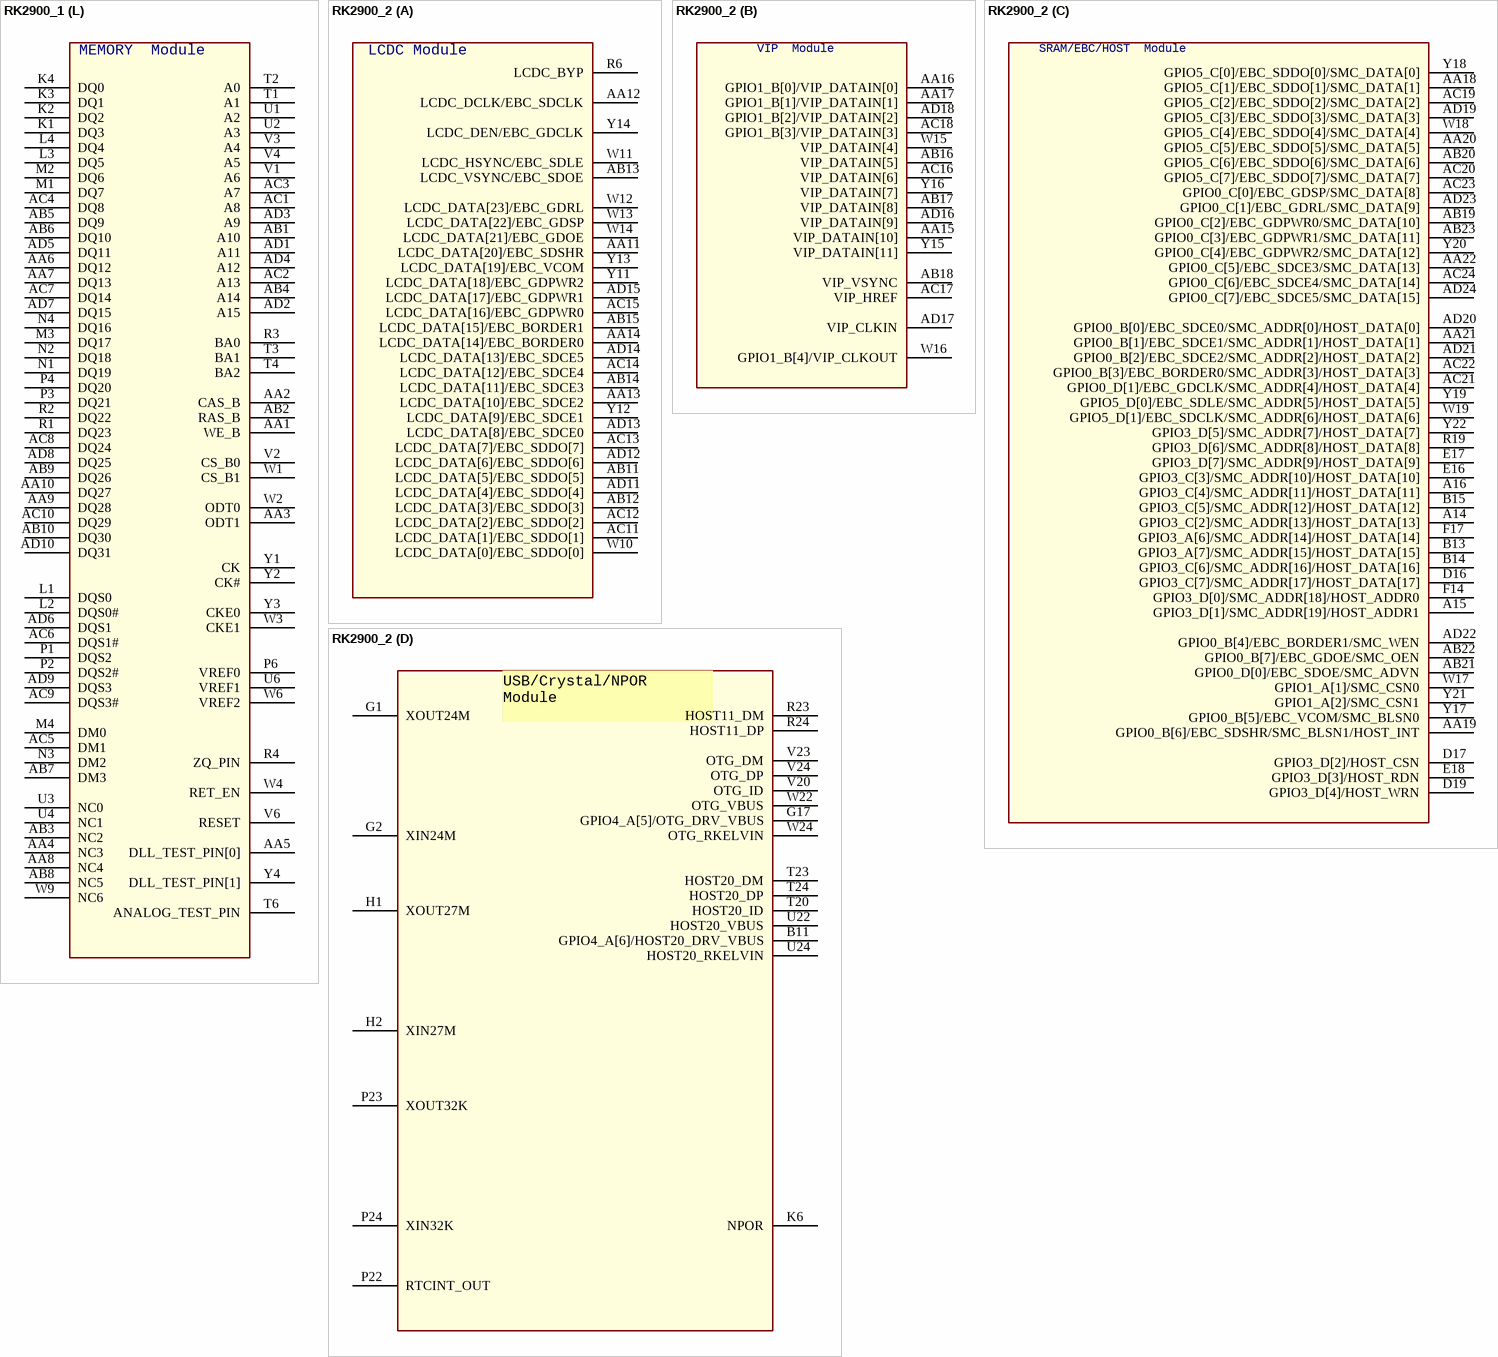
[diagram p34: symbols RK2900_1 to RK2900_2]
## RK2900_1
designator U?
footprint BGA512
part A pins: AA11 LCDC_DATA[20]/EBC_SDSHR, AA12 LCDC_DCLK/EBC_SDCLK, AA13 LCDC_DATA[10]/EBC_SDCE2, AA14 LCDC_DATA[14]/EBC_BORDER0, AB11 LCDC_DATA[5]/EBC_SDDO[5], AB12 LCDC_DATA[3]/EBC_SDDO[3], AB13 LCDC_VSYNC/EBC_SDOE, AB14 LCDC_DATA[11]/EBC_SDCE3, AB15 LCDC_DATA[15]/EBC_BORDER1, AC11 LCDC_DATA[1]/EBC_SDDO[1], AC12 LCDC_DATA[2]/EBC_SDDO[2], AC13 LCDC_DATA[7]/EBC_SDDO[7], AC14 LCDC_DATA[12]/EBC_SDCE4, AC15 LCDC_DATA[16]/EBC_GDPWR0, AD11 LCDC_DATA[4]/EBC_SDDO[4], AD12 LCDC_DATA[6]/EBC_SDDO[6], AD13 LCDC_DATA[8]/EBC_SDCE0, AD14 LCDC_DATA[13]/EBC_SDCE5, AD15 LCDC_DATA[17]/EBC_GDPWR1, R6 LCDC_BYP, W10 LCDC_DATA[0]/EBC_SDDO[0], W11 LCDC_HSYNC/EBC_SDLE, W12 LCDC_DATA[23]/EBC_GDRL, W13 LCDC_DATA[22]/EBC_GDSP, W14 LCDC_DATA[21]/EBC_GDOE, Y11 LCDC_DATA[18]/EBC_GDPWR2, Y12 LCDC_DATA[9]/EBC_SDCE1, Y13 LCDC_DATA[19]/EBC_VCOM, Y14 LCDC_DEN/EBC_GDCLK
part B pins: AA15 VIP_DATAIN[10], AA16 GPIO1_B[0]/VIP_DATAIN[0], AA17 GPIO1_B[1]/VIP_DATAIN[1], AB16 VIP_DATAIN[5], AB17 VIP_DATAIN[8], AB18 VIP_VSYNC, AC16 VIP_DATAIN[6], AC17 VIP_HREF, AC18 GPIO1_B[3]/VIP_DATAIN[3], AD16 VIP_DATAIN[9], AD17 VIP_CLKIN, AD18 GPIO1_B[2]/VIP_DATAIN[2], W15 VIP_DATAIN[4], W16 GPIO1_B[4]/VIP_CLKOUT, Y15 VIP_DATAIN[11], Y16 VIP_DATAIN[7]
part C pins: A14 GPIO3_C[2]/SMC_ADDR[13]/HOST_DATA[13], A15 GPIO3_D[1]/SMC_ADDR[19]/HOST_ADDR1, A16 GPIO3_C[4]/SMC_ADDR[11]/HOST_DATA[11], AA18 GPIO5_C[1]/EBC_SDDO[1]/SMC_DATA[1], AA19 GPIO0_B[6]/EBC_SDSHR/SMC_BLSN1/HOST_INT, AA20 GPIO5_C[5]/EBC_SDDO[5]/SMC_DATA[5], AA21 GPIO0_B[1]/EBC_SDCE1/SMC_ADDR[1]/HOST_DATA[1], AA22 GPIO0_C[5]/EBC_SDCE3/SMC_DATA[13], AB19 GPIO0_C[2]/EBC_GDPWR0/SMC_DATA[10], AB20 GPIO5_C[6]/EBC_SDDO[6]/SMC_DATA[6], AB21 GPIO0_D[0]/EBC_SDOE/SMC_ADVN, AB22 GPIO0_B[7]/EBC_GDOE/SMC_OEN, AB23 GPIO0_C[3]/EBC_GDPWR1/SMC_DATA[11], AC19 GPIO5_C[2]/EBC_SDDO[2]/SMC_DATA[2], AC20 GPIO5_C[7]/EBC_SDDO[7]/SMC_DATA[7], AC21 GPIO0_D[1]/EBC_GDCLK/SMC_ADDR[4]/HOST_DATA[4], AC22 GPIO0_B[3]/EBC_BORDER0/SMC_ADDR[3]/HOST_DATA[3], AC23 GPIO0_C[0]/EBC_GDSP/SMC_DATA[8], AC24 GPIO0_C[6]/EBC_SDCE4/SMC_DATA[14], AD19 GPIO5_C[3]/EBC_SDDO[3]/SMC_DATA[3], AD20 GPIO0_B[0]/EBC_SDCE0/SMC_ADDR[0]/HOST_DATA[0], AD21 GPIO0_B[2]/EBC_SDCE2/SMC_ADDR[2]/HOST_DATA[2], AD22 GPIO0_B[4]/EBC_BORDER1/SMC_WEN, AD23 GPIO0_C[1]/EBC_GDRL/SMC_DATA[9], AD24 GPIO0_C[7]/EBC_SDCE5/SMC_DATA[15], B13 GPIO3_A[7]/SMC_ADDR[15]/HOST_DATA[15], B14 GPIO3_C[6]/SMC_ADDR[16]/HOST_DATA[16], B15 GPIO3_C[5]/SMC_ADDR[12]/HOST_DATA[12], D16 GPIO3_C[7]/SMC_ADDR[17]/HOST_DATA[17], D17 GPIO3_D[2]/HOST_CSN, D19 GPIO3_D[4]/HOST_WRN, E16 GPIO3_C[3]/SMC_ADDR[10]/HOST_DATA[10], E17 GPIO3_D[7]/SMC_ADDR[9]/HOST_DATA[9], E18 GPIO3_D[3]/HOST_RDN, F14 GPIO3_D[0]/SMC_ADDR[18]/HOST_ADDR0, F17 GPIO3_A[6]/SMC_ADDR[14]/HOST_DATA[14], R19 GPIO3_D[6]/SMC_ADDR[8]/HOST_DATA[8], W17 GPIO1_A[1]/SMC_CSN0, W18 GPIO5_C[4]/EBC_SDDO[4]/SMC_DATA[4], W19 GPIO5_D[1]/EBC_SDCLK/SMC_ADDR[6]/HOST_DATA[6], Y17 GPIO0_B[5]/EBC_VCOM/SMC_BLSN0, Y18 GPIO5_C[0]/EBC_SDDO[0]/SMC_DATA[0], Y19 GPIO5_D[0]/EBC_SDLE/SMC_ADDR[5]/HOST_DATA[5], Y20 GPIO0_C[4]/EBC_GDPWR2/SMC_DATA[12], Y21 GPIO1_A[2]/SMC_CSN1, Y22 GPIO3_D[5]/SMC_ADDR[7]/HOST_DATA[7]
part D pins: B11 GPIO4_A[6]/HOST20_DRV_VBUS, G1 XOUT24M, G2 XIN24M, G17 GPIO4_A[5]/OTG_DRV_VBUS, H1 XOUT27M, H2 XIN27M, K6 NPOR, P22 RTCINT_OUT, P23 XOUT32K, P24 XIN32K, R23 HOST11_DM, R24 HOST11_DP, T20 HOST20_ID, T23 HOST20_DM, T24 HOST20_DP, U22 HOST20_VBUS, U24 HOST20_RKELVIN, V20 OTG_ID, V23 OTG_DM, V24 OTG_DP, W22 OTG_VBUS, W24 OTG_RKELVIN
part E pins: A9 GPIO1_A[5]/EMMC_PWR_EN/PWM3, D23 GPIO3_B[7]/EMMC_DATA5, E22 GPIO3_B[0]/EMMC_CLKOUT, F21 GPIO3_C[0]/EMMC_DATA6, F22 GPIO3_B[2]/EMMC_DATA0, F23 GPIO3_B[4]/EMMC_DATA2, F24 GPIO3_B[5]/EMMC_DATA3, G21 GPIO3_C[1]/EMMC_DATA7, G23 GPIO3_B[6]/EMMC_DATA4, H21 GPIO3_B[1]/EMMC_CMD, H24 GPIO3_B[3]/EMMC_DATA1, J19 GPIO0_D[6]/FLASH_CSN5, J20 GPIO1_A[0]/FLASH_CSN7/MDDR_TQ, J21 GPIO0_A[5]/FLASH_DQS, J22 GPIO0_D[5]/FLASH_CSN4, J23 GPIO4_B[2]/FLASH_DATA[10], J24 GPIO4_B[3]/FLASH_DATA[11], K19 FLASH_WP, K20 FLASH_WRN, K21 GPIO4_B[6]/FLASH_DATA[14], K22 GPIO0_D[3]/FLASH_CSN2, K23 GPIO0_D[4]/FLASH_CSN3, K24 GPIO0_D[2]/FLASH_CSN1, L19 FLASH_DATA[6], L20 GPIO4_B[0]/FLASH_DATA[8], L21 FLASH_DATA[7], L22 FLASH_DATA[2], L23 FLASH_DATA[3], L24 GPIO0_D[7]/FLASH_CSN6, M19 GPIO4_B[7]/FLASH_DATA[15], M20 GPIO4_B[5]/FLASH_DATA[13], M21 FLASH_CLE, M22 GPIO4_B[1]/FLASH_DATA[9], M23 FLASH_DATA[5], M24 FLASH_CSN0, N19 FLASH_DATA[1], N20 FLASH_RDY, N21 FLASH_RDN, N22 GPIO4_B[4]/FLASH_DATA[12], N23 FLASH_DATA[0], N24 FLASH_DATA[4], P19 FLASH_ALE
part F pins: A6 GPIO5_D[6]/SDMMC1_PWR_EN, A7 GPIO5_D[5]/SDMMC0_PWR_EN, B10 GPIO2_A[2]/SDMMC0_DETECT_N, B24 GPIO1_D[4]/SDMMC0_DATA2, C22 GPIO2_A[0]/SDMMC0_DATA6, C23 GPIO1_D[6]/SDMMC0_DATA4, D20 GPIO1_D[2]/SDMMC0_DATA0, D22 GPIO1_D[0]/SDMMC0_CLKOUT, D24 GPIO1_C[2]/SDMMC1_CMD, E20 GPIO1_D[7]/SDMMC0_DATA5, E23 GPIO2_A[1]/SDMMC0_DATA7, G19 GPIO1_D[5]/SDMMC0_DATA3, G20 GPIO1_D[1]/SDMMC0_CMD, G22 GPIO1_D[3]/SDMMC0_DATA1, G24 GPIO1_C[7]/SDMMC1_CLKOUT, H18 GPIO1_C[5]/SDMMC1_DATA2, H19 GPIO1_C[6]/SDMMC1_DATA3, H22 GPIO1_C[3]/SDMMC1_DATA0, H23 GPIO1_C[4]/SDMMC1_DATA1
part G pins: A18 GPIO4_C[5]/RMII_CRS_DVALID/MII_RXD_VALID, A20 GPIO4_C[0]/RMII_CLKOUT/RMII_CLKIN, A22 GPIO4_C[1]/RMII_TX_EN/MII_TX_EN, B18 GPIO5_A[3]/MII_TX_CLKIN, B23 GPIO4_C[6]/RMII_RXD1/MII_RXD1, C18 GPIO4_C[4]/RMII_RX_ERR/MII_RX_ERR, C19 GPIO4_C[2]/RMII_TXD1/MII_TXD1, D11 GPIO0_A[7]/MII_MDCLK, D18 GPIO0_A[6]/MII_MD, D21 GPIO4_C[3]/RMII_TXD0/MII_TXD0, E19 GPIO4_C[7]/RMII_RXD0/MII_RXD0, K5 TRST_N, L5 TCK, L6 TDI, M6 TMS, M7 TDO
part H pins: A17 GPIO5_B[3]/HSADC_DATA6, A19 GPIO5_A[7]/HSADC_DATA2, B17 GPIO5_B[2]/HSADC_DATA5, B19 GPIO5_B[5]/HSADC_DATA8/TS_VALID, B20 GPIO5_A[5]/HSADC_DATA0, C13 GPIO5_B[6]/HSADC_DATA9/TS_FAIL, C16 GPIO5_A[4]/TS_SYNC, C17 GPIO5_B[4]/HSADC_DATA7, C20 GPIO5_B[1]/HSADC_DATA4, E21 GPIO5_B[0]/HSADC_DATA3, F18 GPIO5_A[6]/HSADC_DATA1, F19 GPIO5_B[7]/HSADC_CLKOUT/GPS_CLK
part I pins: A3 GPIO1_C[0]/UART0_CTS_N/SDMMC1_DETECT_N, A4 GPIO3_A[5]/I2S1_LRCK_TX, A5 GPIO3_A[4]/I2S1_SDO, A8 GPIO2_B[2]/UART3_SIN, A10 GPIO1_A[4]/EMMC_WRITE_PRT/SPI0_CSN1, A12 GPIO1_A[6]/I2C1_SDA, A13 GPIO2_C[5]/SPI1_CSN0, A21 GPIO2_D[2]/I2S0_LRCK_RX/MII_TX_ERR, A23 GPIO2_D[5]/I2S0_SDO1/MII_RXD3, A24 GPIO2_D[6]/I2S0_SDO2/MII_TXD2, B4 GPIO2_A[7]/UART2_RTS_N, B5 GPIO3_A[3]/I2S1_SDI, B6 GPIO3_A[1]/I2S1_SCLK, B8 GPIO5_D[3]/I2C2_SDA, B12 GPIO1_A[7]/I2C1_SCL, B16 GPIO2_C[6]/SPI1_TXD, B21 GPIO4_D[7]/I2S0_LRCK_TX1, B22 GPIO2_D[3]/I2S0_SDI/MII_COL, C4 GPIO1_C[1]/UART0_RTS_N/SDMMC1_WRITE_PRT, C5 GPIO2_A[6]/UART2_CTS_N, C6 GPIO3_A[2]/I2S1_LRCK_RX, C7 GPIO2_A[4]/UART1_SIN, C9 GPIO2_B[6]/I2C0_SDA, C14 GPIO2_C[7]/SPI1_RXD, C15 GPIO4_A[7]/SPDIF_TX, C21 GPIO2_D[4]/I2S0_SDO0/MII_RXD2, C24 GPIO2_D[7]/I2S0_SDO3/MII_TXD3, D5 GPIO1_B[7]/UART0_SOUT, D6 GPIO2_B[4]/UART3_CTS_N/I2C3_SDA, D7 GPIO3_A[0]/I2S1_CLK, D8 GPIO1_B[6]/UART0_SIN, D9 GPIO5_D[4]/I2C2_SCL, D10 GPIO2_B[7]/I2C0_SCL, D14 GPIO2_C[0]/SPI0_CLK, D15 GPIO2_C[3]/SPI0_RXD, E6 GPIO2_B[0]/UART2_SIN, E7 GPIO2_B[5]/UART3_RTS_N/I2C3_SCL, E8 GPIO2_B[1]/UART2_SOUT, E9 GPIO2_A[5]/UART1_SOUT, E14 GPIO2_C[1]/SPI0_CSN0, E15 GPIO2_C[2]/SPI0_TXD, E24 GPIO2_D[0]/I2S0_CLK/MII_RX_CLKIN, F8 GPIO2_B[3]/UART3_SOUT, F15 GPIO1_A[3]/EMMC_DETECT_N/SPI1_CSN1, F16 GPIO2_C[4]/SPI1_CLK, F20 GPIO4_D[6]/I2S0_LRCK_TX0, H20 GPIO2_D[1]/I2S0_SCLK/MII_CRS
part J pins: A1 GPIO6_A[0], A2 GPIO6_B[7], A11 GPIO6_C[2], AA23 SARADC_AIN[0], AA24 SARADC_AIN[3], B1 GPIO6_B[6], B2 GPIO6_B[5], B3 GPIO6_A[1], B7 GPIO5_D[2]/PWM1/UART1_SIR_IN, B9 GPIO2_A[3]/SDMMC0_WRITE_PRT/PWM2/UART1_SIR_OUT, C1 GPIO6_A[5], C2 GPIO6_B[4], C3 GPIO6_A[2], C8 GPIO1_B[5]/PWM0, C10 GPIO4_D[4], C11 GPIO6_C[6], C12 GPIO6_C[0], D1 GPIO6_A[6], D2 GPIO6_A[7], D3 GPIO6_B[3], D4 GPIO6_A[3], D12 GPIO4_D[0], D13 GPIO6_C[3], E1 GPIO6_B[0], E2 GPIO5_A[0], E3 GPIO6_B[2], E4 GPIO5_A[2], E5 GPIO6_A[4], E10 GPIO6_C[5], E11 GPIO4_D[1], E12 GPIO6_C[1], E13 GPIO6_C[7], F1 GPIO6_B[1], F2 GPIO0_A[1], F3 GPIO5_A[1], F4 GPIO0_A[0], F9 GPIO4_D[3], F10 GPIO4_D[2], F11 GPIO4_D[5], F12 GPIO5_D[7], F13 GPIO6_C[4], G3 GPIO0_A[2], G4 GPIO0_A[4], H3 GPIO0_A[3], H4 GPIO4_A[3], J1 GPIO4_A[0], J2 GPIO4_A[1], J3 GPIO4_A[2], J4 GPIO4_A[4], N6 BTMODE, P7 EWAKEUP_STOP, P20 VDDCORE_EFUSE, R20 EFUSE_VQPS, T7 EWAKEUP_POWER, T19 VDDIO_EFUSE, V7 TEST, V8 GPIO6_D[2], V9 GPIO6_D[0], W7 GPIO6_D[3], W8 GPIO6_D[1], Y23 SARADC_AIN[1], Y24 SARADC_AIN[2]
part K pins: AB24 VDDA_SARADC, F5 AVDD_DPLL, F6 AHVDD_APLL, F7 AHVSS_APLL, G5 DVDD_APLL, G6 AVSS_DPLL, G7 DVSS_APLL, G8 VDDIO_AP1, G9 VDDIO_AP0, G10 VDDCORE, G11 VDDIO6, G12 VDDCORE, G13 VDDIO5, G14 VDDCORE, G15 VDDIO4, G16 VDDCORE, G18 VDDIO3, H5 DVDD_DPLL, H6 DVSS_DPLL, H7 DVSS_CGPLL, J5 AVDD_CGPLL, J6 DVDD_CGPLL, J7 AVSS_CGPLL, J18 VDDCORE, K7 VDDIO0, K10 GND, K11 GND, K12 GND, K13 GND, K14 GND, K15 GND, K18 VDDIO2, L7 VDDCORE, L10 GND, L11 GND, L12 GND, L13 GND, L14 GND, L15 GND, L18 VDDCORE, M5 VSSIO_DDR0, M10 GND, M11 GND, M12 GND, M13 GND, M14 GND, M15 GND, M18 VDDIO_FLASH1, N5 VDDIO_DDR0, N7 VDDCORE, N10 GND, N11 GND, N12 GND, N13 GND, N14 GND, N15 GND, N18 VDDCORE, P5 VSSIO_DDR1, P10 GND, P11 GND, P12 GND, P13 GND, P14 GND, P15 GND, P18 VDDIO_FLASH0, P21 VDDIO_RTC, R5 VDDIO_DDR1, R7 VDDCORE, R10 GND, R11 GND, R12 GND, R13 GND, R14 GND, R15 GND, R18 VDDCORE, R21 VSSIO_UHOST11, R22 VDDIO_UHOST11, T5 VSSIO_DDR2, T18 VDDIO1, T21 HOST20_VSSA, T22 HOST_VDD25, U5 VDDIO_DDR2, U7 VDDCORE, U18 VDDCORE_RTC, U19 HOST20_DVDD, U20 HOST20_VSSAC, U21 HOST20_DVSS, U23 HOST20_VDD33, V5 VSSIO_DDR3, V10 VDDCORE, V11 VDDIO_LCD0, V12 VDDCORE, V13 VDDIO_LCD1, V14 VDDCORE, V15 VDDIO_VIP, V16 VDDCORE, V17 VDDIO_SMC0, V18 VDDIO_SMC1, V19 OTG_DVDD, V21 OTG_VSSA, V22 OTG_VDD25, W5 VDDIO_DDR3, W20 OTG_VSSAC, W21 OTG_DVSS, W23 OTG_VDD33, Y5 VSSIO_DDR4, Y6 VDDIO_DDR4, Y7 VSSIO_DDR5, Y8 VDDIO_DDR5, Y9 VSSIO_DDR6, Y10 VDDIO_DDR6
part L pins: AA1 WE_B, AA2 CAS_B, AA3 ODT1, AA4 NC3, AA5 DLL_TEST_PIN[0], AA6 DQ12, AA7 DQ13, AA8 NC4, AA9 DQ28, AA10 DQ27, AB1 A10, AB2 RAS_B, AB3 NC2, AB4 A14, AB5 DQ9, AB6 DQ10, AB7 DM3, AB8 NC5, AB9 DQ26, AB10 DQ30, AC1 A8, AC2 A13, AC3 A7, AC4 DQ8, AC5 DM1, AC6 DQS1#, AC7 DQ14, AC8 DQ24, AC9 DQS3#, AC10 DQ29, AD1 A11, AD2 A15, AD3 A9, AD4 A12, AD5 DQ11, AD6 DQS1, AD7 DQ15, AD8 DQ25, AD9 DQS3, AD10 DQ31, K1 DQ3, K2 DQ2, K3 DQ1, K4 DQ0, L1 DQS0, L2 DQS0#, L3 DQ5, L4 DQ4, M1 DQ7, M2 DQ6, M3 DQ17, M4 DM0, N1 DQ19, N2 DQ18, N3 DM2, N4 DQ16, P1 DQS2, P2 DQS2#, P3 DQ21, P4 DQ20, P6 VREF0, R1 DQ23, R2 DQ22, R3 BA0, R4 ZQ_PIN, T1 A1, T2 A0, T3 BA1, T4 BA2, T6 ANALOG_TEST_PIN, U1 A2, U2 A3, U3 NC0, U4 NC1, U6 VREF1, V1 A6, V2 CS_B0, V3 A4, V4 A5, V6 RESET, W1 CS_B1, W2 ODT0, W3 CKE1, W4 RET_EN, W6 VREF2, W9 NC6, Y1 CK, Y2 CK#, Y3 CKE0, Y4 DLL_TEST_PIN[1]




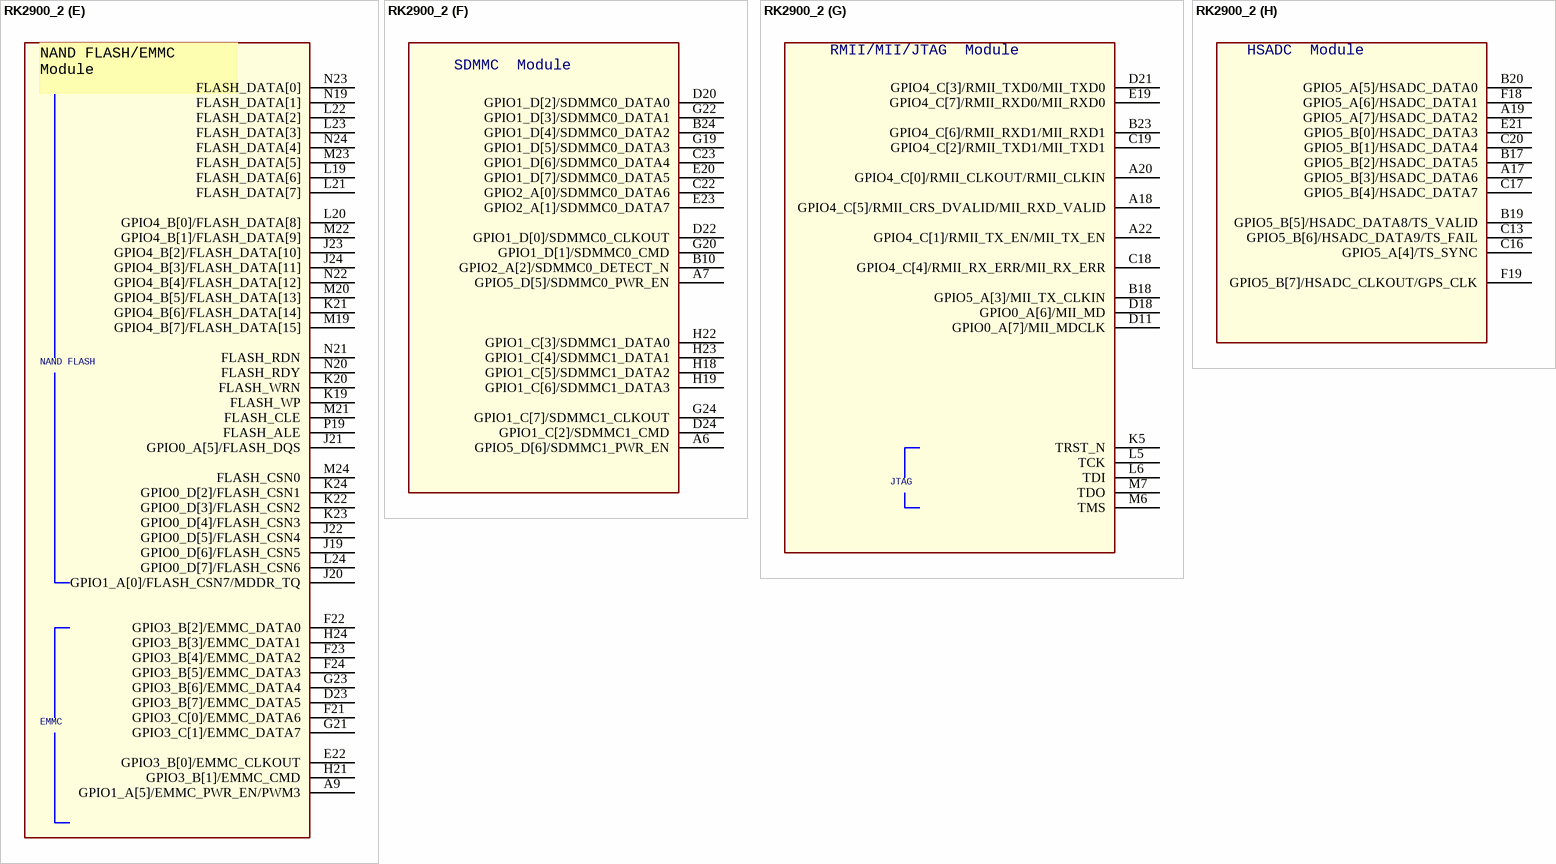
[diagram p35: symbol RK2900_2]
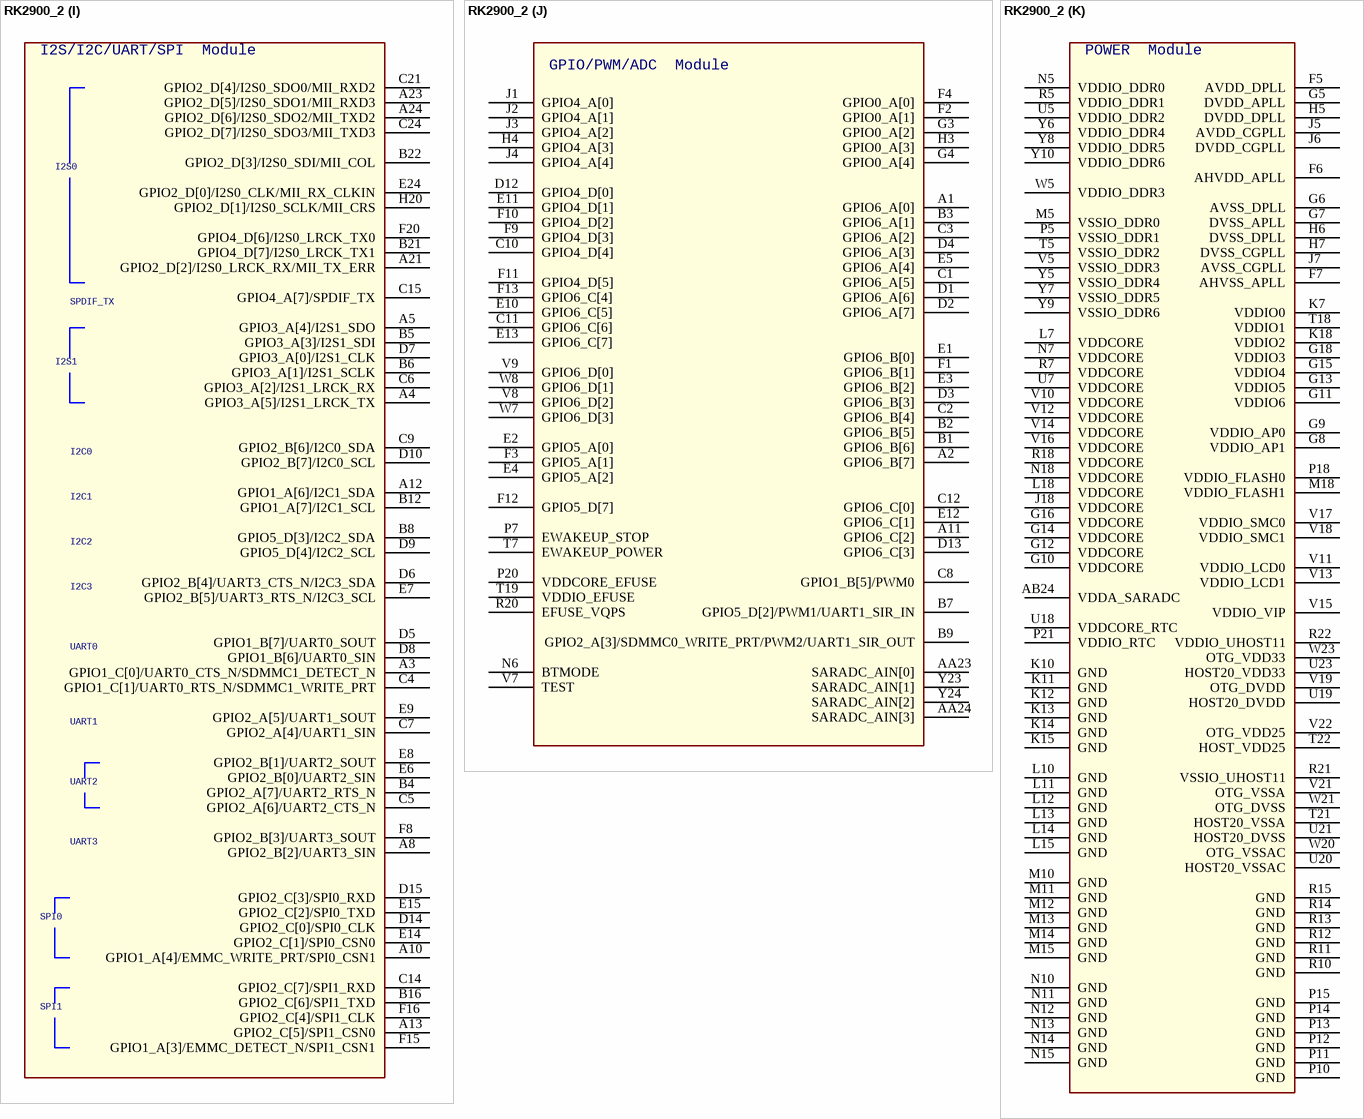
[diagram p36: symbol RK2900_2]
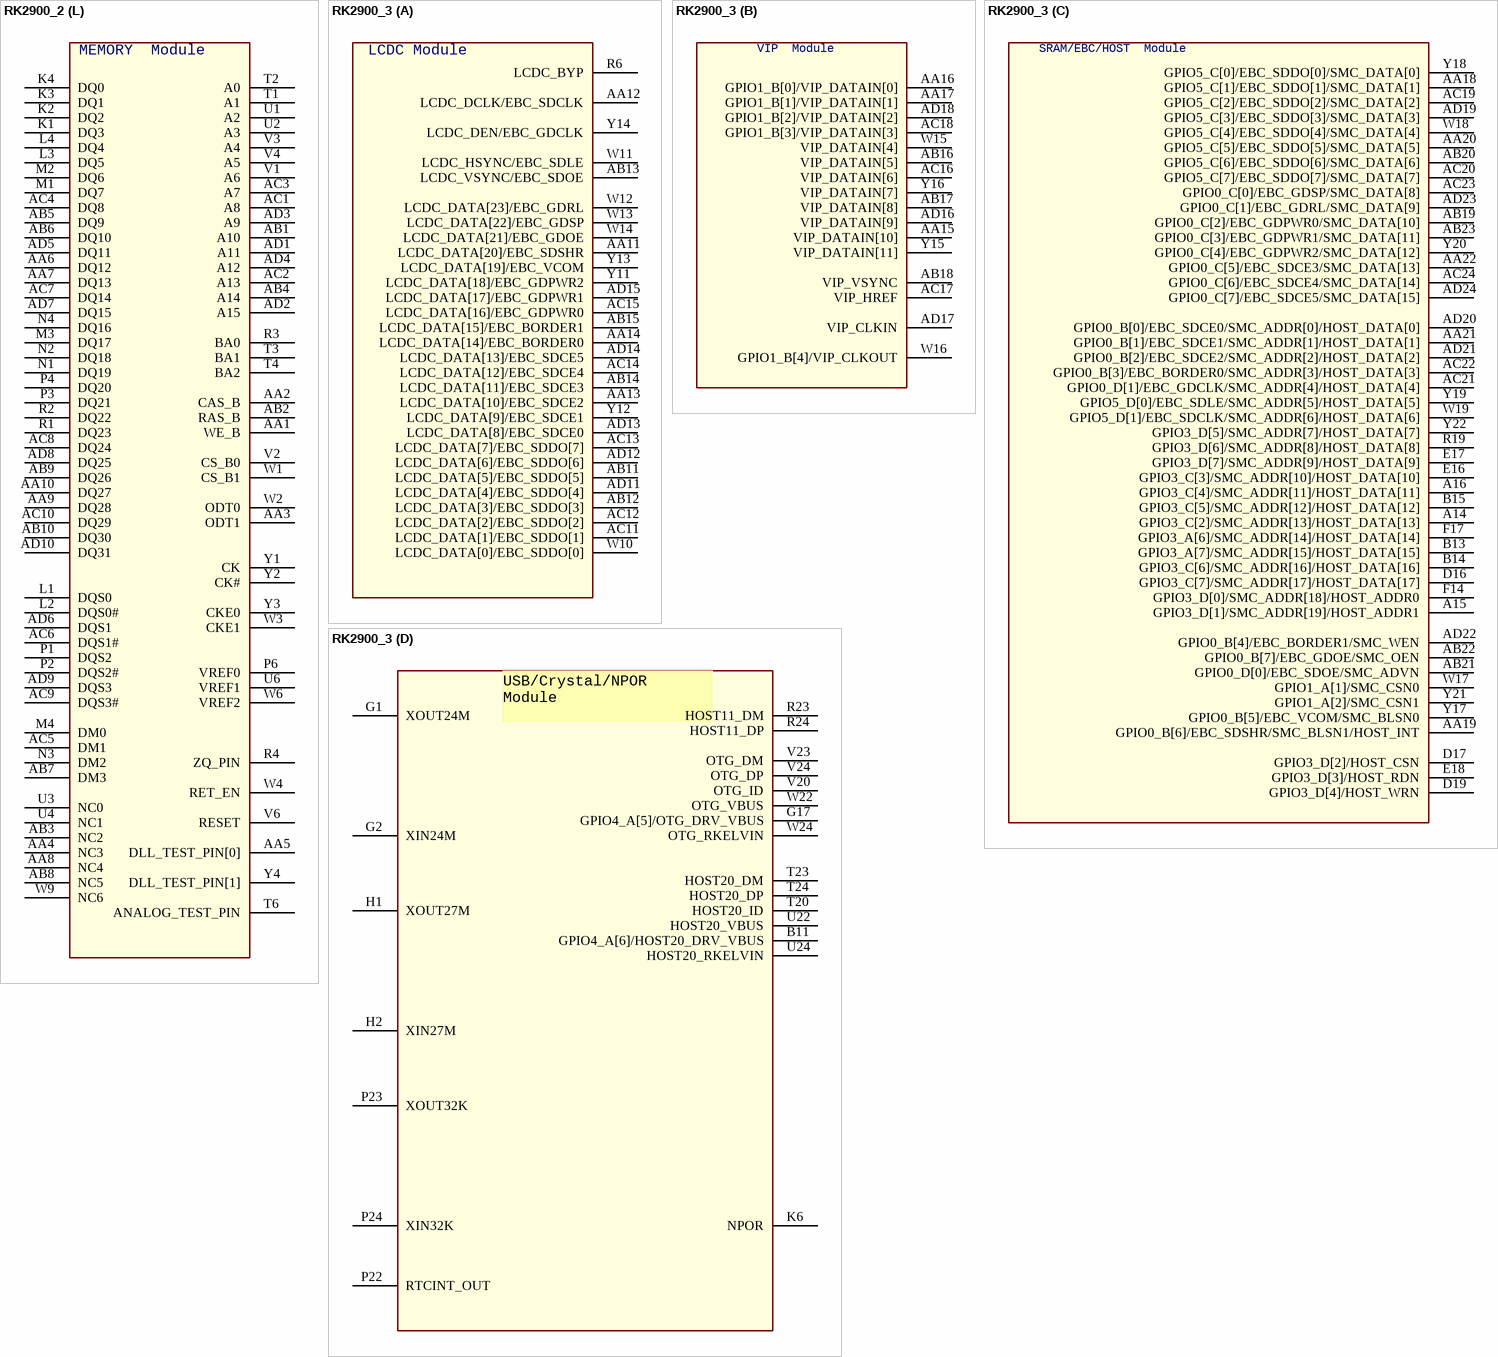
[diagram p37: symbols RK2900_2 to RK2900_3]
## RK2900_2
designator U?
footprint BGA512
part A pins: AA11 LCDC_DATA[20]/EBC_SDSHR, AA12 LCDC_DCLK/EBC_SDCLK, AA13 LCDC_DATA[10]/EBC_SDCE2, AA14 LCDC_DATA[14]/EBC_BORDER0, AB11 LCDC_DATA[5]/EBC_SDDO[5], AB12 LCDC_DATA[3]/EBC_SDDO[3], AB13 LCDC_VSYNC/EBC_SDOE, AB14 LCDC_DATA[11]/EBC_SDCE3, AB15 LCDC_DATA[15]/EBC_BORDER1, AC11 LCDC_DATA[1]/EBC_SDDO[1], AC12 LCDC_DATA[2]/EBC_SDDO[2], AC13 LCDC_DATA[7]/EBC_SDDO[7], AC14 LCDC_DATA[12]/EBC_SDCE4, AC15 LCDC_DATA[16]/EBC_GDPWR0, AD11 LCDC_DATA[4]/EBC_SDDO[4], AD12 LCDC_DATA[6]/EBC_SDDO[6], AD13 LCDC_DATA[8]/EBC_SDCE0, AD14 LCDC_DATA[13]/EBC_SDCE5, AD15 LCDC_DATA[17]/EBC_GDPWR1, R6 LCDC_BYP, W10 LCDC_DATA[0]/EBC_SDDO[0], W11 LCDC_HSYNC/EBC_SDLE, W12 LCDC_DATA[23]/EBC_GDRL, W13 LCDC_DATA[22]/EBC_GDSP, W14 LCDC_DATA[21]/EBC_GDOE, Y11 LCDC_DATA[18]/EBC_GDPWR2, Y12 LCDC_DATA[9]/EBC_SDCE1, Y13 LCDC_DATA[19]/EBC_VCOM, Y14 LCDC_DEN/EBC_GDCLK
part B pins: AA15 VIP_DATAIN[10], AA16 GPIO1_B[0]/VIP_DATAIN[0], AA17 GPIO1_B[1]/VIP_DATAIN[1], AB16 VIP_DATAIN[5], AB17 VIP_DATAIN[8], AB18 VIP_VSYNC, AC16 VIP_DATAIN[6], AC17 VIP_HREF, AC18 GPIO1_B[3]/VIP_DATAIN[3], AD16 VIP_DATAIN[9], AD17 VIP_CLKIN, AD18 GPIO1_B[2]/VIP_DATAIN[2], W15 VIP_DATAIN[4], W16 GPIO1_B[4]/VIP_CLKOUT, Y15 VIP_DATAIN[11], Y16 VIP_DATAIN[7]
part C pins: A14 GPIO3_C[2]/SMC_ADDR[13]/HOST_DATA[13], A15 GPIO3_D[1]/SMC_ADDR[19]/HOST_ADDR1, A16 GPIO3_C[4]/SMC_ADDR[11]/HOST_DATA[11], AA18 GPIO5_C[1]/EBC_SDDO[1]/SMC_DATA[1], AA19 GPIO0_B[6]/EBC_SDSHR/SMC_BLSN1/HOST_INT, AA20 GPIO5_C[5]/EBC_SDDO[5]/SMC_DATA[5], AA21 GPIO0_B[1]/EBC_SDCE1/SMC_ADDR[1]/HOST_DATA[1], AA22 GPIO0_C[5]/EBC_SDCE3/SMC_DATA[13], AB19 GPIO0_C[2]/EBC_GDPWR0/SMC_DATA[10], AB20 GPIO5_C[6]/EBC_SDDO[6]/SMC_DATA[6], AB21 GPIO0_D[0]/EBC_SDOE/SMC_ADVN, AB22 GPIO0_B[7]/EBC_GDOE/SMC_OEN, AB23 GPIO0_C[3]/EBC_GDPWR1/SMC_DATA[11], AC19 GPIO5_C[2]/EBC_SDDO[2]/SMC_DATA[2], AC20 GPIO5_C[7]/EBC_SDDO[7]/SMC_DATA[7], AC21 GPIO0_D[1]/EBC_GDCLK/SMC_ADDR[4]/HOST_DATA[4], AC22 GPIO0_B[3]/EBC_BORDER0/SMC_ADDR[3]/HOST_DATA[3], AC23 GPIO0_C[0]/EBC_GDSP/SMC_DATA[8], AC24 GPIO0_C[6]/EBC_SDCE4/SMC_DATA[14], AD19 GPIO5_C[3]/EBC_SDDO[3]/SMC_DATA[3], AD20 GPIO0_B[0]/EBC_SDCE0/SMC_ADDR[0]/HOST_DATA[0], AD21 GPIO0_B[2]/EBC_SDCE2/SMC_ADDR[2]/HOST_DATA[2], AD22 GPIO0_B[4]/EBC_BORDER1/SMC_WEN, AD23 GPIO0_C[1]/EBC_GDRL/SMC_DATA[9], AD24 GPIO0_C[7]/EBC_SDCE5/SMC_DATA[15], B13 GPIO3_A[7]/SMC_ADDR[15]/HOST_DATA[15], B14 GPIO3_C[6]/SMC_ADDR[16]/HOST_DATA[16], B15 GPIO3_C[5]/SMC_ADDR[12]/HOST_DATA[12], D16 GPIO3_C[7]/SMC_ADDR[17]/HOST_DATA[17], D17 GPIO3_D[2]/HOST_CSN, D19 GPIO3_D[4]/HOST_WRN, E16 GPIO3_C[3]/SMC_ADDR[10]/HOST_DATA[10], E17 GPIO3_D[7]/SMC_ADDR[9]/HOST_DATA[9], E18 GPIO3_D[3]/HOST_RDN, F14 GPIO3_D[0]/SMC_ADDR[18]/HOST_ADDR0, F17 GPIO3_A[6]/SMC_ADDR[14]/HOST_DATA[14], R19 GPIO3_D[6]/SMC_ADDR[8]/HOST_DATA[8], W17 GPIO1_A[1]/SMC_CSN0, W18 GPIO5_C[4]/EBC_SDDO[4]/SMC_DATA[4], W19 GPIO5_D[1]/EBC_SDCLK/SMC_ADDR[6]/HOST_DATA[6], Y17 GPIO0_B[5]/EBC_VCOM/SMC_BLSN0, Y18 GPIO5_C[0]/EBC_SDDO[0]/SMC_DATA[0], Y19 GPIO5_D[0]/EBC_SDLE/SMC_ADDR[5]/HOST_DATA[5], Y20 GPIO0_C[4]/EBC_GDPWR2/SMC_DATA[12], Y21 GPIO1_A[2]/SMC_CSN1, Y22 GPIO3_D[5]/SMC_ADDR[7]/HOST_DATA[7]
part D pins: B11 GPIO4_A[6]/HOST20_DRV_VBUS, G1 XOUT24M, G2 XIN24M, G17 GPIO4_A[5]/OTG_DRV_VBUS, H1 XOUT27M, H2 XIN27M, K6 NPOR, P22 RTCINT_OUT, P23 XOUT32K, P24 XIN32K, R23 HOST11_DM, R24 HOST11_DP, T20 HOST20_ID, T23 HOST20_DM, T24 HOST20_DP, U22 HOST20_VBUS, U24 HOST20_RKELVIN, V20 OTG_ID, V23 OTG_DM, V24 OTG_DP, W22 OTG_VBUS, W24 OTG_RKELVIN
part E pins: A9 GPIO1_A[5]/EMMC_PWR_EN/PWM3, D23 GPIO3_B[7]/EMMC_DATA5, E22 GPIO3_B[0]/EMMC_CLKOUT, F21 GPIO3_C[0]/EMMC_DATA6, F22 GPIO3_B[2]/EMMC_DATA0, F23 GPIO3_B[4]/EMMC_DATA2, F24 GPIO3_B[5]/EMMC_DATA3, G21 GPIO3_C[1]/EMMC_DATA7, G23 GPIO3_B[6]/EMMC_DATA4, H21 GPIO3_B[1]/EMMC_CMD, H24 GPIO3_B[3]/EMMC_DATA1, J19 GPIO0_D[6]/FLASH_CSN5, J20 GPIO1_A[0]/FLASH_CSN7/MDDR_TQ, J21 GPIO0_A[5]/FLASH_DQS, J22 GPIO0_D[5]/FLASH_CSN4, J23 GPIO4_B[2]/FLASH_DATA[10], J24 GPIO4_B[3]/FLASH_DATA[11], K19 FLASH_WP, K20 FLASH_WRN, K21 GPIO4_B[6]/FLASH_DATA[14], K22 GPIO0_D[3]/FLASH_CSN2, K23 GPIO0_D[4]/FLASH_CSN3, K24 GPIO0_D[2]/FLASH_CSN1, L19 FLASH_DATA[6], L20 GPIO4_B[0]/FLASH_DATA[8], L21 FLASH_DATA[7], L22 FLASH_DATA[2], L23 FLASH_DATA[3], L24 GPIO0_D[7]/FLASH_CSN6, M19 GPIO4_B[7]/FLASH_DATA[15], M20 GPIO4_B[5]/FLASH_DATA[13], M21 FLASH_CLE, M22 GPIO4_B[1]/FLASH_DATA[9], M23 FLASH_DATA[5], M24 FLASH_CSN0, N19 FLASH_DATA[1], N20 FLASH_RDY, N21 FLASH_RDN, N22 GPIO4_B[4]/FLASH_DATA[12], N23 FLASH_DATA[0], N24 FLASH_DATA[4], P19 FLASH_ALE
part F pins: A6 GPIO5_D[6]/SDMMC1_PWR_EN, A7 GPIO5_D[5]/SDMMC0_PWR_EN, B10 GPIO2_A[2]/SDMMC0_DETECT_N, B24 GPIO1_D[4]/SDMMC0_DATA2, C22 GPIO2_A[0]/SDMMC0_DATA6, C23 GPIO1_D[6]/SDMMC0_DATA4, D20 GPIO1_D[2]/SDMMC0_DATA0, D22 GPIO1_D[0]/SDMMC0_CLKOUT, D24 GPIO1_C[2]/SDMMC1_CMD, E20 GPIO1_D[7]/SDMMC0_DATA5, E23 GPIO2_A[1]/SDMMC0_DATA7, G19 GPIO1_D[5]/SDMMC0_DATA3, G20 GPIO1_D[1]/SDMMC0_CMD, G22 GPIO1_D[3]/SDMMC0_DATA1, G24 GPIO1_C[7]/SDMMC1_CLKOUT, H18 GPIO1_C[5]/SDMMC1_DATA2, H19 GPIO1_C[6]/SDMMC1_DATA3, H22 GPIO1_C[3]/SDMMC1_DATA0, H23 GPIO1_C[4]/SDMMC1_DATA1
part G pins: A18 GPIO4_C[5]/RMII_CRS_DVALID/MII_RXD_VALID, A20 GPIO4_C[0]/RMII_CLKOUT/RMII_CLKIN, A22 GPIO4_C[1]/RMII_TX_EN/MII_TX_EN, B18 GPIO5_A[3]/MII_TX_CLKIN, B23 GPIO4_C[6]/RMII_RXD1/MII_RXD1, C18 GPIO4_C[4]/RMII_RX_ERR/MII_RX_ERR, C19 GPIO4_C[2]/RMII_TXD1/MII_TXD1, D11 GPIO0_A[7]/MII_MDCLK, D18 GPIO0_A[6]/MII_MD, D21 GPIO4_C[3]/RMII_TXD0/MII_TXD0, E19 GPIO4_C[7]/RMII_RXD0/MII_RXD0, K5 TRST_N, L5 TCK, L6 TDI, M6 TMS, M7 TDO
part H pins: A17 GPIO5_B[3]/HSADC_DATA6, A19 GPIO5_A[7]/HSADC_DATA2, B17 GPIO5_B[2]/HSADC_DATA5, B19 GPIO5_B[5]/HSADC_DATA8/TS_VALID, B20 GPIO5_A[5]/HSADC_DATA0, C13 GPIO5_B[6]/HSADC_DATA9/TS_FAIL, C16 GPIO5_A[4]/TS_SYNC, C17 GPIO5_B[4]/HSADC_DATA7, C20 GPIO5_B[1]/HSADC_DATA4, E21 GPIO5_B[0]/HSADC_DATA3, F18 GPIO5_A[6]/HSADC_DATA1, F19 GPIO5_B[7]/HSADC_CLKOUT/GPS_CLK
part I pins: A3 GPIO1_C[0]/UART0_CTS_N/SDMMC1_DETECT_N, A4 GPIO3_A[5]/I2S1_LRCK_TX, A5 GPIO3_A[4]/I2S1_SDO, A8 GPIO2_B[2]/UART3_SIN, A10 GPIO1_A[4]/EMMC_WRITE_PRT/SPI0_CSN1, A12 GPIO1_A[6]/I2C1_SDA, A13 GPIO2_C[5]/SPI1_CSN0, A21 GPIO2_D[2]/I2S0_LRCK_RX/MII_TX_ERR, A23 GPIO2_D[5]/I2S0_SDO1/MII_RXD3, A24 GPIO2_D[6]/I2S0_SDO2/MII_TXD2, B4 GPIO2_A[7]/UART2_RTS_N, B5 GPIO3_A[3]/I2S1_SDI, B6 GPIO3_A[1]/I2S1_SCLK, B8 GPIO5_D[3]/I2C2_SDA, B12 GPIO1_A[7]/I2C1_SCL, B16 GPIO2_C[6]/SPI1_TXD, B21 GPIO4_D[7]/I2S0_LRCK_TX1, B22 GPIO2_D[3]/I2S0_SDI/MII_COL, C4 GPIO1_C[1]/UART0_RTS_N/SDMMC1_WRITE_PRT, C5 GPIO2_A[6]/UART2_CTS_N, C6 GPIO3_A[2]/I2S1_LRCK_RX, C7 GPIO2_A[4]/UART1_SIN, C9 GPIO2_B[6]/I2C0_SDA, C14 GPIO2_C[7]/SPI1_RXD, C15 GPIO4_A[7]/SPDIF_TX, C21 GPIO2_D[4]/I2S0_SDO0/MII_RXD2, C24 GPIO2_D[7]/I2S0_SDO3/MII_TXD3, D5 GPIO1_B[7]/UART0_SOUT, D6 GPIO2_B[4]/UART3_CTS_N/I2C3_SDA, D7 GPIO3_A[0]/I2S1_CLK, D8 GPIO1_B[6]/UART0_SIN, D9 GPIO5_D[4]/I2C2_SCL, D10 GPIO2_B[7]/I2C0_SCL, D14 GPIO2_C[0]/SPI0_CLK, D15 GPIO2_C[3]/SPI0_RXD, E6 GPIO2_B[0]/UART2_SIN, E7 GPIO2_B[5]/UART3_RTS_N/I2C3_SCL, E8 GPIO2_B[1]/UART2_SOUT, E9 GPIO2_A[5]/UART1_SOUT, E14 GPIO2_C[1]/SPI0_CSN0, E15 GPIO2_C[2]/SPI0_TXD, E24 GPIO2_D[0]/I2S0_CLK/MII_RX_CLKIN, F8 GPIO2_B[3]/UART3_SOUT, F15 GPIO1_A[3]/EMMC_DETECT_N/SPI1_CSN1, F16 GPIO2_C[4]/SPI1_CLK, F20 GPIO4_D[6]/I2S0_LRCK_TX0, H20 GPIO2_D[1]/I2S0_SCLK/MII_CRS
part J pins: A1 GPIO6_A[0], A2 GPIO6_B[7], A11 GPIO6_C[2], AA23 SARADC_AIN[0], AA24 SARADC_AIN[3], B1 GPIO6_B[6], B2 GPIO6_B[5], B3 GPIO6_A[1], B7 GPIO5_D[2]/PWM1/UART1_SIR_IN, B9 GPIO2_A[3]/SDMMC0_WRITE_PRT/PWM2/UART1_SIR_OUT, C1 GPIO6_A[5], C2 GPIO6_B[4], C3 GPIO6_A[2], C8 GPIO1_B[5]/PWM0, C10 GPIO4_D[4], C11 GPIO6_C[6], C12 GPIO6_C[0], D1 GPIO6_A[6], D2 GPIO6_A[7], D3 GPIO6_B[3], D4 GPIO6_A[3], D12 GPIO4_D[0], D13 GPIO6_C[3], E1 GPIO6_B[0], E2 GPIO5_A[0], E3 GPIO6_B[2], E4 GPIO5_A[2], E5 GPIO6_A[4], E10 GPIO6_C[5], E11 GPIO4_D[1], E12 GPIO6_C[1], E13 GPIO6_C[7], F1 GPIO6_B[1], F2 GPIO0_A[1], F3 GPIO5_A[1], F4 GPIO0_A[0], F9 GPIO4_D[3], F10 GPIO4_D[2], F11 GPIO4_D[5], F12 GPIO5_D[7], F13 GPIO6_C[4], G3 GPIO0_A[2], G4 GPIO0_A[4], H3 GPIO0_A[3], H4 GPIO4_A[3], J1 GPIO4_A[0], J2 GPIO4_A[1], J3 GPIO4_A[2], J4 GPIO4_A[4], N6 BTMODE, P7 EWAKEUP_STOP, P20 VDDCORE_EFUSE, R20 EFUSE_VQPS, T7 EWAKEUP_POWER, T19 VDDIO_EFUSE, V7 TEST, V8 GPIO6_D[2], V9 GPIO6_D[0], W7 GPIO6_D[3], W8 GPIO6_D[1], Y23 SARADC_AIN[1], Y24 SARADC_AIN[2]
part K pins: AB24 VDDA_SARADC, F5 AVDD_DPLL, F6 AHVDD_APLL, F7 AHVSS_APLL, G5 DVDD_APLL, G6 AVSS_DPLL, G7 DVSS_APLL, G8 VDDIO_AP1, G9 VDDIO_AP0, G10 VDDCORE, G11 VDDIO6, G12 VDDCORE, G13 VDDIO5, G14 VDDCORE, G15 VDDIO4, G16 VDDCORE, G18 VDDIO3, H5 DVDD_DPLL, H6 DVSS_DPLL, H7 DVSS_CGPLL, J5 AVDD_CGPLL, J6 DVDD_CGPLL, J7 AVSS_CGPLL, J18 VDDCORE, K7 VDDIO0, K10 GND, K11 GND, K12 GND, K13 GND, K14 GND, K15 GND, K18 VDDIO2, L7 VDDCORE, L10 GND, L11 GND, L12 GND, L13 GND, L14 GND, L15 GND, L18 VDDCORE, M5 VSSIO_DDR0, M10 GND, M11 GND, M12 GND, M13 GND, M14 GND, M15 GND, M18 VDDIO_FLASH1, N5 VDDIO_DDR0, N7 VDDCORE, N10 GND, N11 GND, N12 GND, N13 GND, N14 GND, N15 GND, N18 VDDCORE, P5 VSSIO_DDR1, P10 GND, P11 GND, P12 GND, P13 GND, P14 GND, P15 GND, P18 VDDIO_FLASH0, P21 VDDIO_RTC, R5 VDDIO_DDR1, R7 VDDCORE, R10 GND, R11 GND, R12 GND, R13 GND, R14 GND, R15 GND, R18 VDDCORE, R21 VSSIO_UHOST11, R22 VDDIO_UHOST11, T5 VSSIO_DDR2, T18 VDDIO1, T21 HOST20_VSSA, T22 HOST_VDD25, U5 VDDIO_DDR2, U7 VDDCORE, U18 VDDCORE_RTC, U19 HOST20_DVDD, U20 HOST20_VSSAC, U21 HOST20_DVSS, U23 HOST20_VDD33, V5 VSSIO_DDR3, V10 VDDCORE, V11 VDDIO_LCD0, V12 VDDCORE, V13 VDDIO_LCD1, V14 VDDCORE, V15 VDDIO_VIP, V16 VDDCORE, V17 VDDIO_SMC0, V18 VDDIO_SMC1, V19 OTG_DVDD, V21 OTG_VSSA, V22 OTG_VDD25, W5 VDDIO_DDR3, W20 OTG_VSSAC, W21 OTG_DVSS, W23 OTG_VDD33, Y5 VSSIO_DDR4, Y6 VDDIO_DDR4, Y7 VSSIO_DDR5, Y8 VDDIO_DDR5, Y9 VSSIO_DDR6, Y10 VDDIO_DDR6
part L pins: AA1 WE_B, AA2 CAS_B, AA3 ODT1, AA4 NC3, AA5 DLL_TEST_PIN[0], AA6 DQ12, AA7 DQ13, AA8 NC4, AA9 DQ28, AA10 DQ27, AB1 A10, AB2 RAS_B, AB3 NC2, AB4 A14, AB5 DQ9, AB6 DQ10, AB7 DM3, AB8 NC5, AB9 DQ26, AB10 DQ30, AC1 A8, AC2 A13, AC3 A7, AC4 DQ8, AC5 DM1, AC6 DQS1#, AC7 DQ14, AC8 DQ24, AC9 DQS3#, AC10 DQ29, AD1 A11, AD2 A15, AD3 A9, AD4 A12, AD5 DQ11, AD6 DQS1, AD7 DQ15, AD8 DQ25, AD9 DQS3, AD10 DQ31, K1 DQ3, K2 DQ2, K3 DQ1, K4 DQ0, L1 DQS0, L2 DQS0#, L3 DQ5, L4 DQ4, M1 DQ7, M2 DQ6, M3 DQ17, M4 DM0, N1 DQ19, N2 DQ18, N3 DM2, N4 DQ16, P1 DQS2, P2 DQS2#, P3 DQ21, P4 DQ20, P6 VREF0, R1 DQ23, R2 DQ22, R3 BA0, R4 ZQ_PIN, T1 A1, T2 A0, T3 BA1, T4 BA2, T6 ANALOG_TEST_PIN, U1 A2, U2 A3, U3 NC0, U4 NC1, U6 VREF1, V1 A6, V2 CS_B0, V3 A4, V4 A5, V6 RESET, W1 CS_B1, W2 ODT0, W3 CKE1, W4 RET_EN, W6 VREF2, W9 NC6, Y1 CK, Y2 CK#, Y3 CKE0, Y4 DLL_TEST_PIN[1]




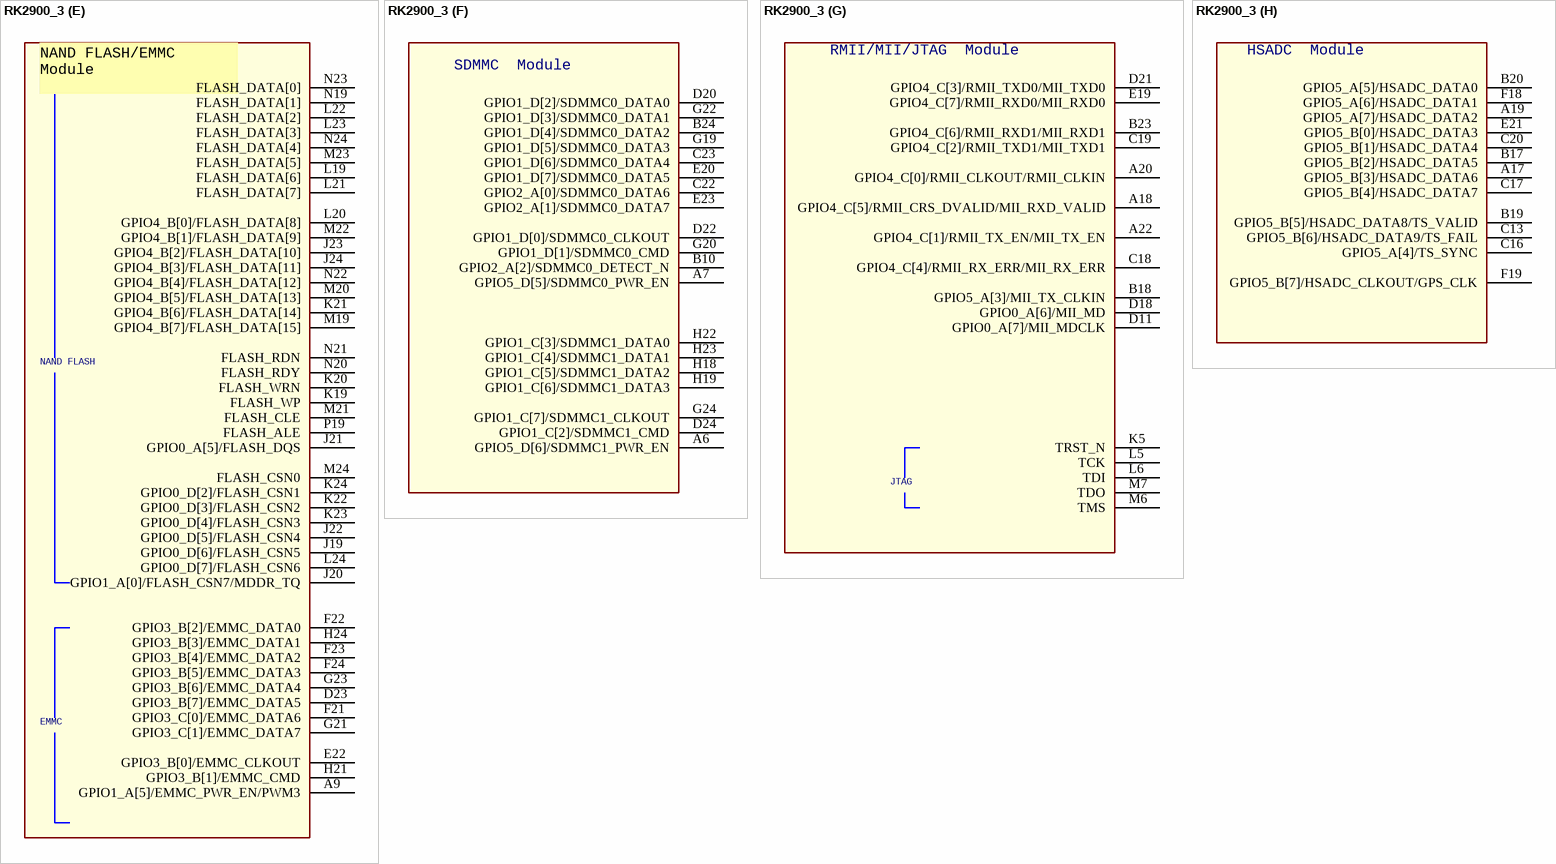
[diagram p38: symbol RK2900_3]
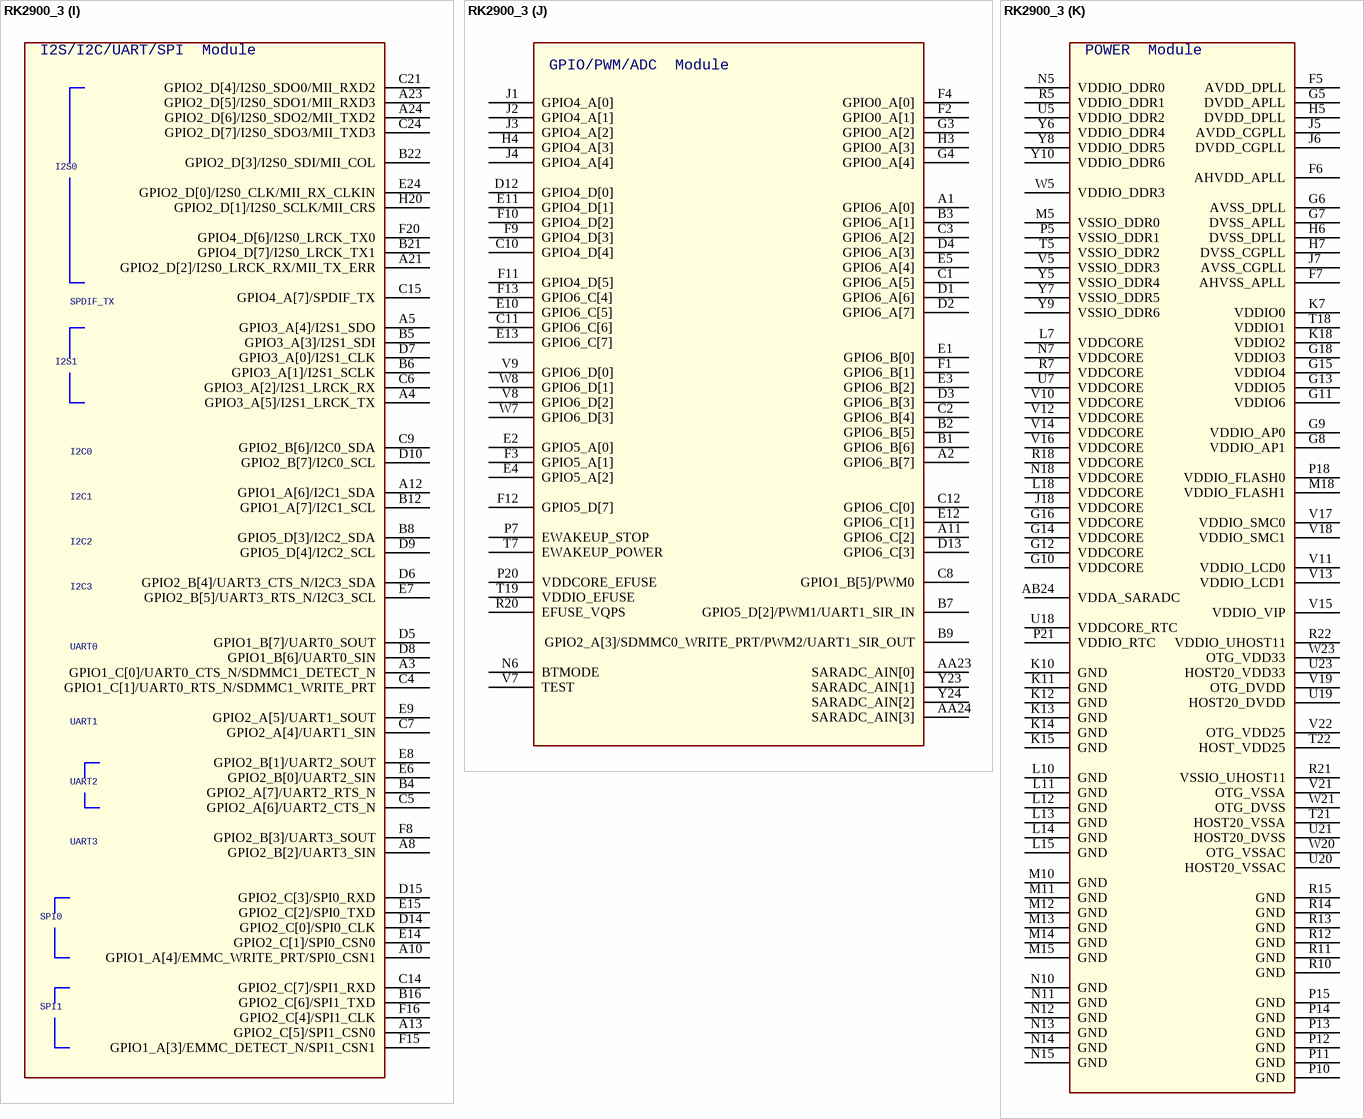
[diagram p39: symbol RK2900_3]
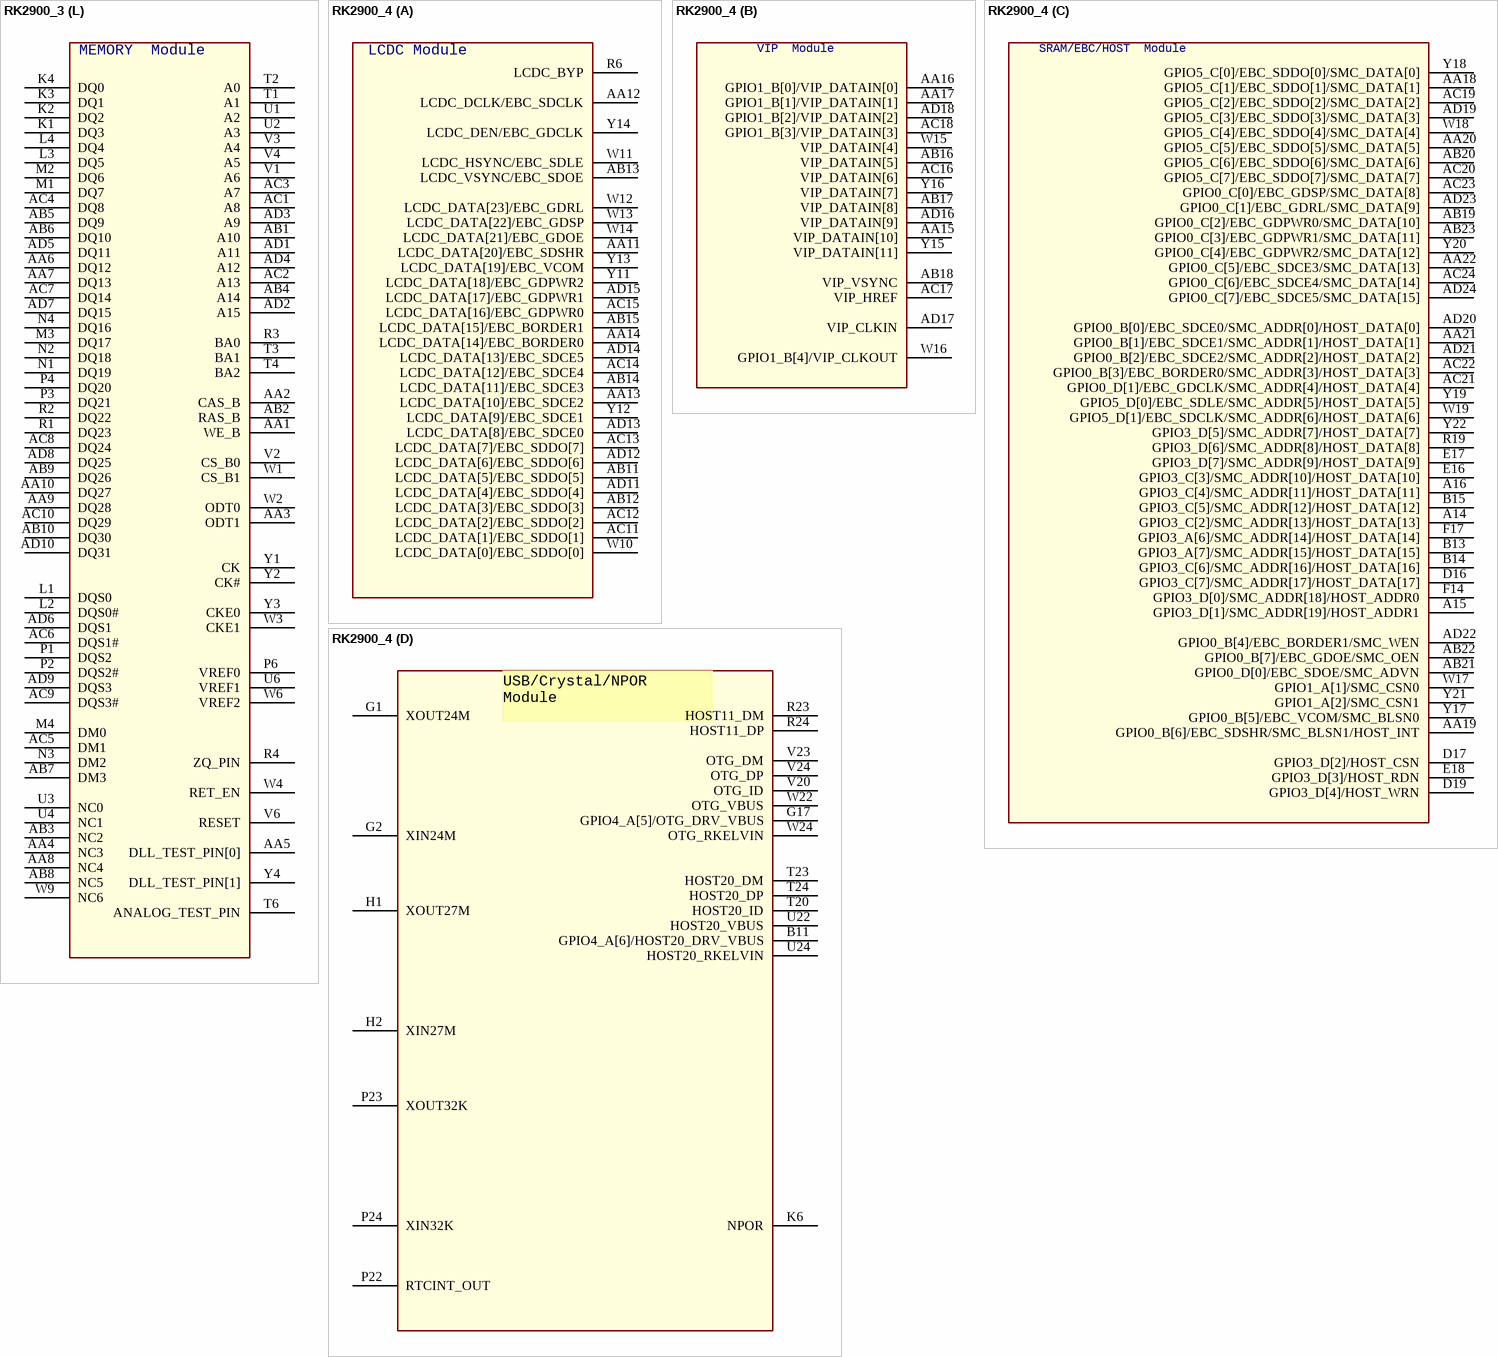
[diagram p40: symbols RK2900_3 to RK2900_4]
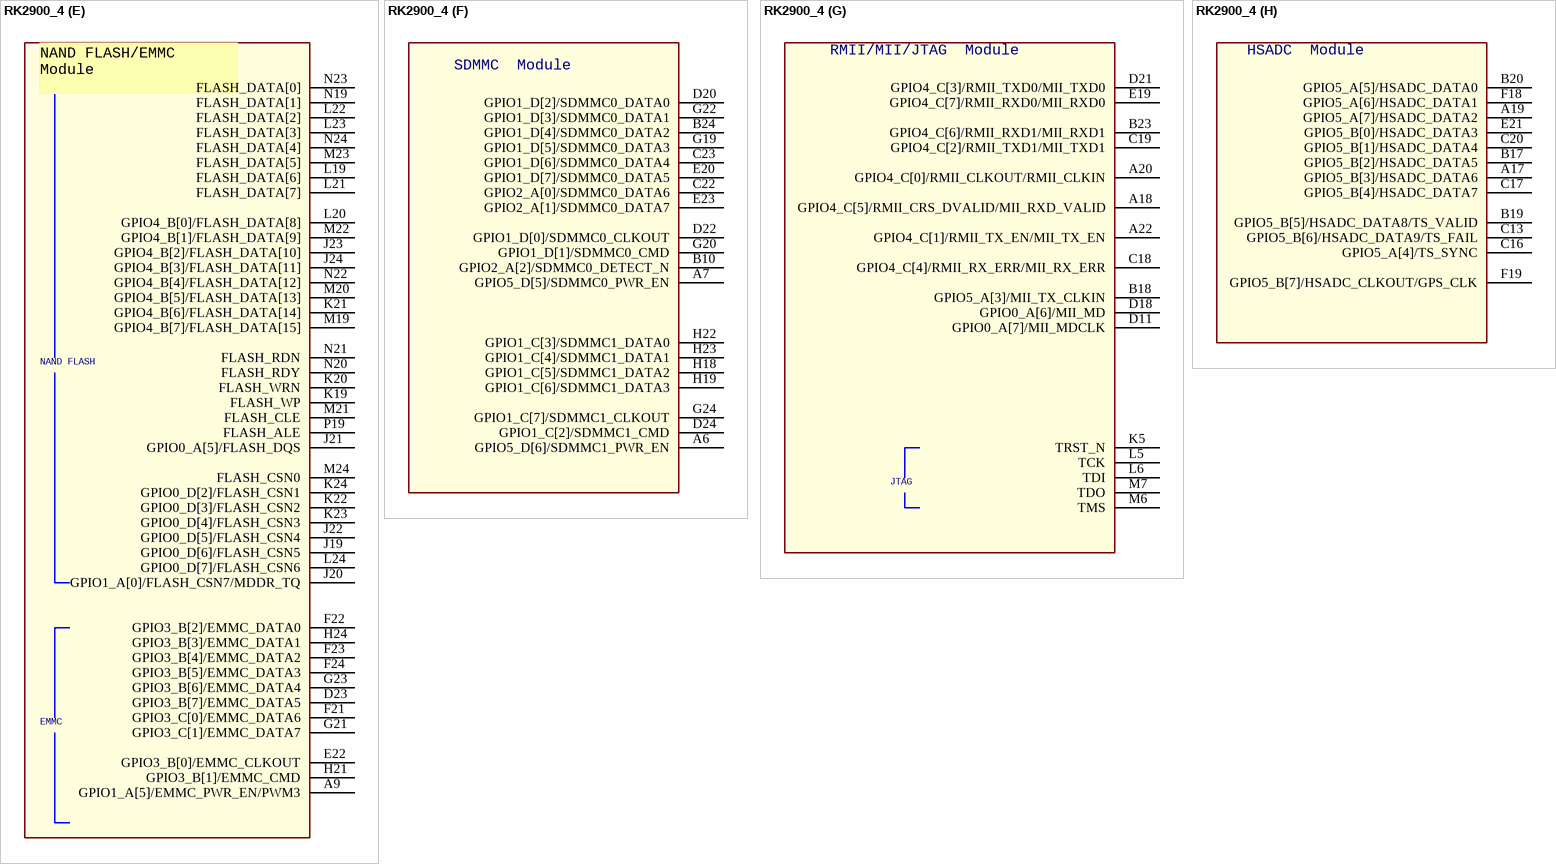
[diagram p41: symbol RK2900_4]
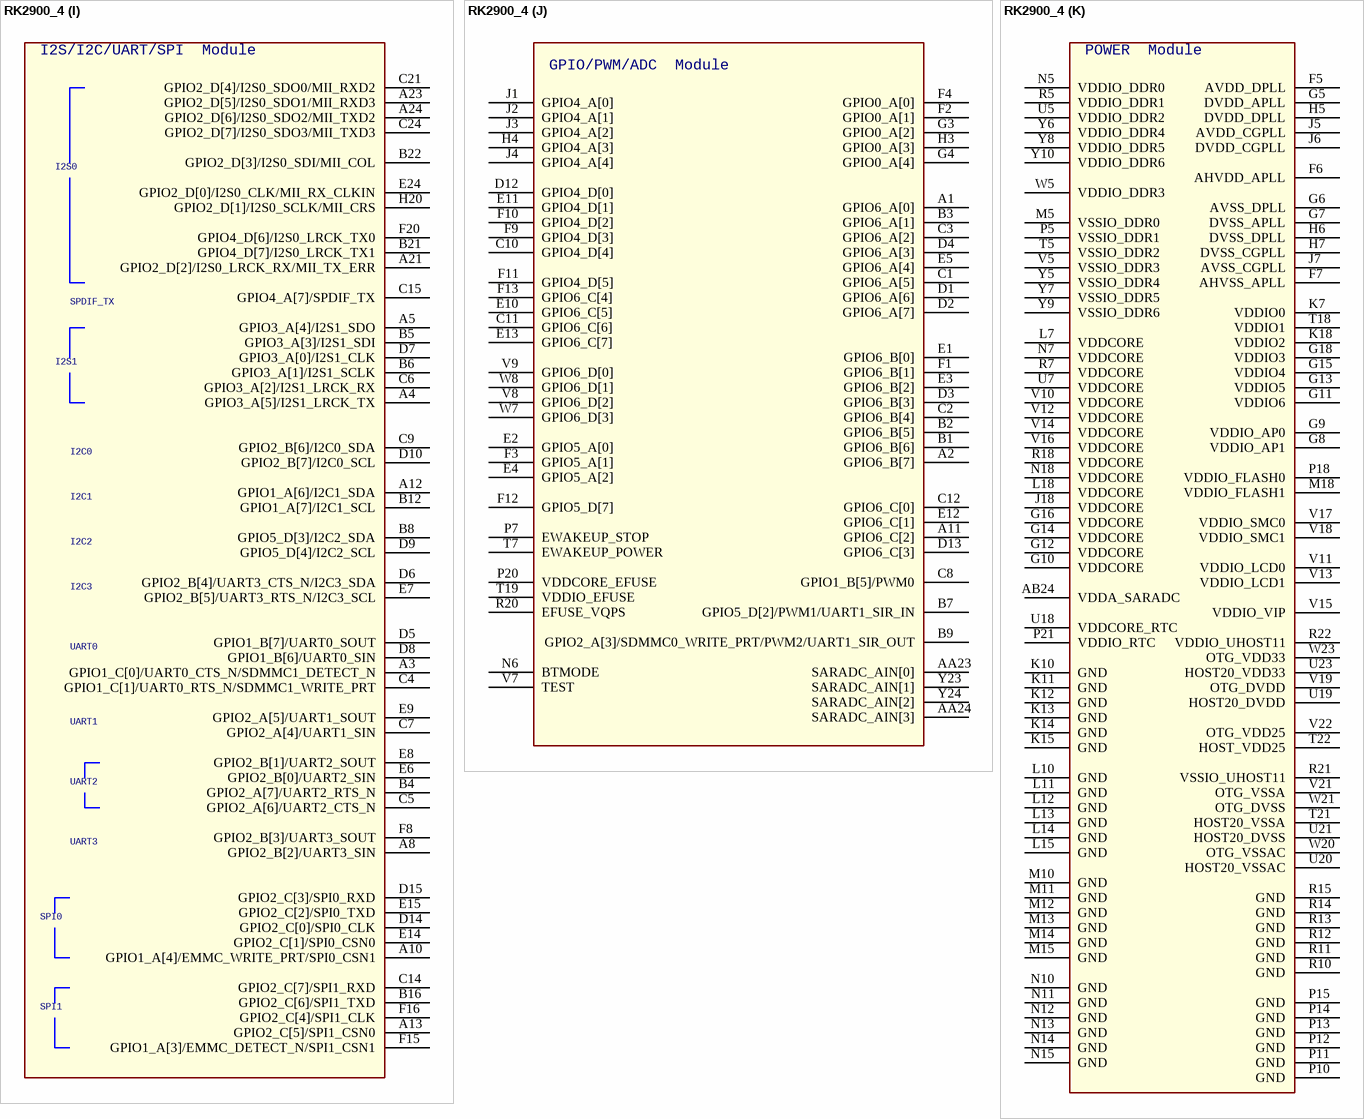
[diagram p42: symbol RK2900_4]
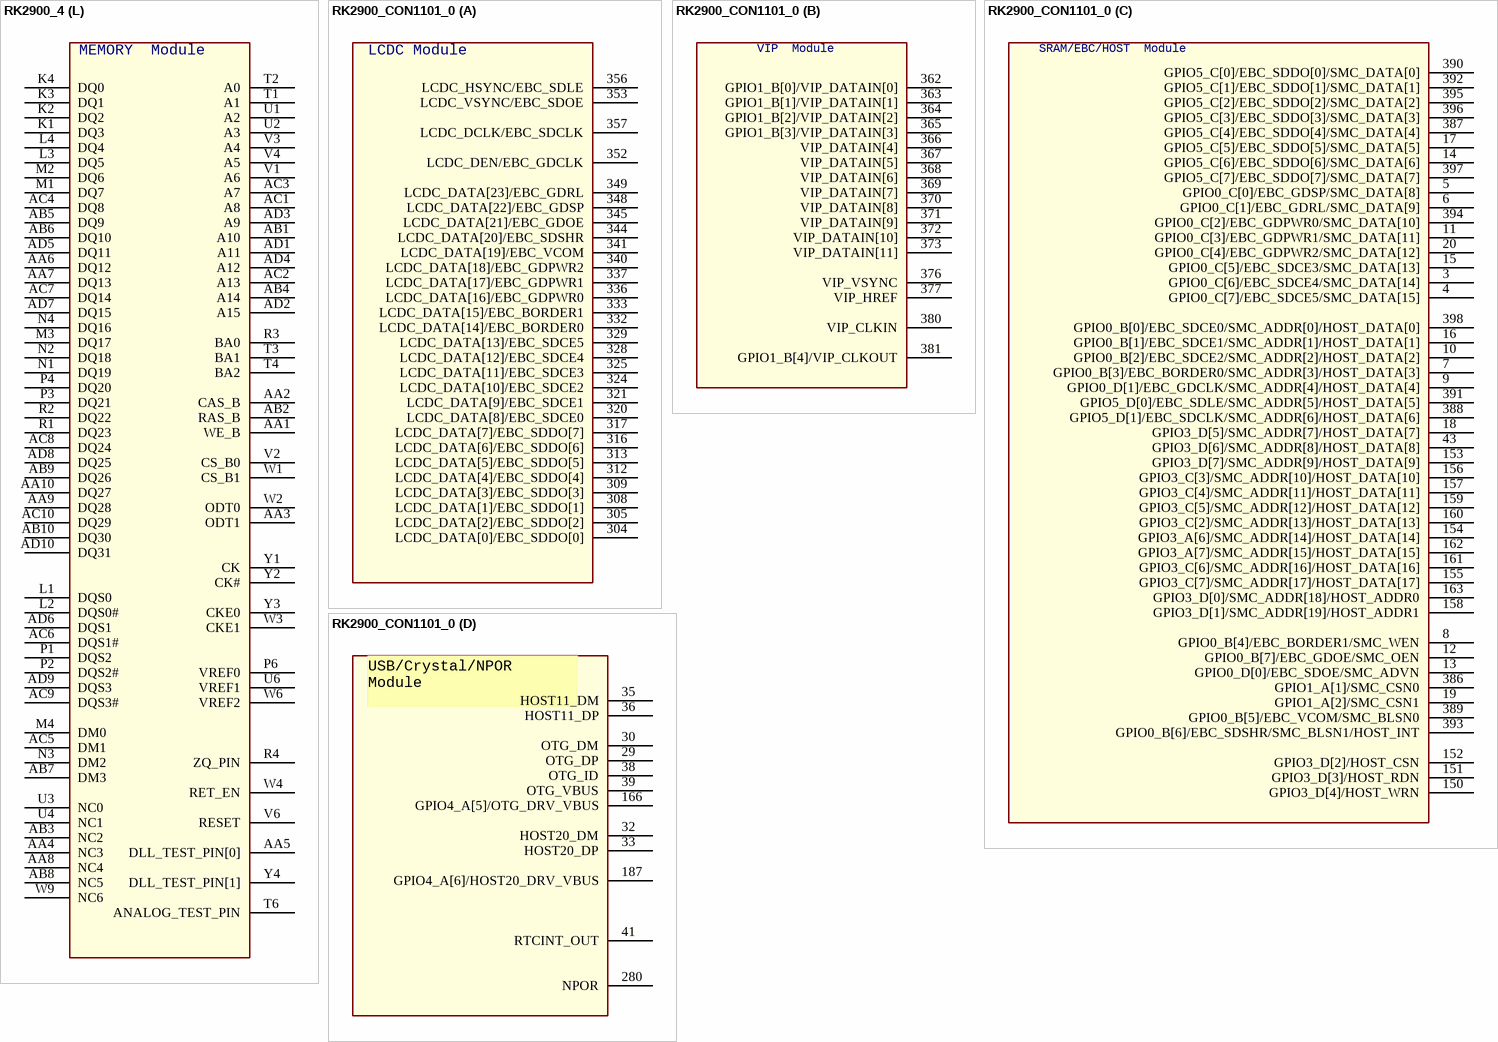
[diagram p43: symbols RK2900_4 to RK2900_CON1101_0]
## RK2900_3
designator U?
footprint BGA512
part A pins: AA11 LCDC_DATA[20]/EBC_SDSHR, AA12 LCDC_DCLK/EBC_SDCLK, AA13 LCDC_DATA[10]/EBC_SDCE2, AA14 LCDC_DATA[14]/EBC_BORDER0, AB11 LCDC_DATA[5]/EBC_SDDO[5], AB12 LCDC_DATA[3]/EBC_SDDO[3], AB13 LCDC_VSYNC/EBC_SDOE, AB14 LCDC_DATA[11]/EBC_SDCE3, AB15 LCDC_DATA[15]/EBC_BORDER1, AC11 LCDC_DATA[1]/EBC_SDDO[1], AC12 LCDC_DATA[2]/EBC_SDDO[2], AC13 LCDC_DATA[7]/EBC_SDDO[7], AC14 LCDC_DATA[12]/EBC_SDCE4, AC15 LCDC_DATA[16]/EBC_GDPWR0, AD11 LCDC_DATA[4]/EBC_SDDO[4], AD12 LCDC_DATA[6]/EBC_SDDO[6], AD13 LCDC_DATA[8]/EBC_SDCE0, AD14 LCDC_DATA[13]/EBC_SDCE5, AD15 LCDC_DATA[17]/EBC_GDPWR1, R6 LCDC_BYP, W10 LCDC_DATA[0]/EBC_SDDO[0], W11 LCDC_HSYNC/EBC_SDLE, W12 LCDC_DATA[23]/EBC_GDRL, W13 LCDC_DATA[22]/EBC_GDSP, W14 LCDC_DATA[21]/EBC_GDOE, Y11 LCDC_DATA[18]/EBC_GDPWR2, Y12 LCDC_DATA[9]/EBC_SDCE1, Y13 LCDC_DATA[19]/EBC_VCOM, Y14 LCDC_DEN/EBC_GDCLK
part B pins: AA15 VIP_DATAIN[10], AA16 GPIO1_B[0]/VIP_DATAIN[0], AA17 GPIO1_B[1]/VIP_DATAIN[1], AB16 VIP_DATAIN[5], AB17 VIP_DATAIN[8], AB18 VIP_VSYNC, AC16 VIP_DATAIN[6], AC17 VIP_HREF, AC18 GPIO1_B[3]/VIP_DATAIN[3], AD16 VIP_DATAIN[9], AD17 VIP_CLKIN, AD18 GPIO1_B[2]/VIP_DATAIN[2], W15 VIP_DATAIN[4], W16 GPIO1_B[4]/VIP_CLKOUT, Y15 VIP_DATAIN[11], Y16 VIP_DATAIN[7]
part C pins: A14 GPIO3_C[2]/SMC_ADDR[13]/HOST_DATA[13], A15 GPIO3_D[1]/SMC_ADDR[19]/HOST_ADDR1, A16 GPIO3_C[4]/SMC_ADDR[11]/HOST_DATA[11], AA18 GPIO5_C[1]/EBC_SDDO[1]/SMC_DATA[1], AA19 GPIO0_B[6]/EBC_SDSHR/SMC_BLSN1/HOST_INT, AA20 GPIO5_C[5]/EBC_SDDO[5]/SMC_DATA[5], AA21 GPIO0_B[1]/EBC_SDCE1/SMC_ADDR[1]/HOST_DATA[1], AA22 GPIO0_C[5]/EBC_SDCE3/SMC_DATA[13], AB19 GPIO0_C[2]/EBC_GDPWR0/SMC_DATA[10], AB20 GPIO5_C[6]/EBC_SDDO[6]/SMC_DATA[6], AB21 GPIO0_D[0]/EBC_SDOE/SMC_ADVN, AB22 GPIO0_B[7]/EBC_GDOE/SMC_OEN, AB23 GPIO0_C[3]/EBC_GDPWR1/SMC_DATA[11], AC19 GPIO5_C[2]/EBC_SDDO[2]/SMC_DATA[2], AC20 GPIO5_C[7]/EBC_SDDO[7]/SMC_DATA[7], AC21 GPIO0_D[1]/EBC_GDCLK/SMC_ADDR[4]/HOST_DATA[4], AC22 GPIO0_B[3]/EBC_BORDER0/SMC_ADDR[3]/HOST_DATA[3], AC23 GPIO0_C[0]/EBC_GDSP/SMC_DATA[8], AC24 GPIO0_C[6]/EBC_SDCE4/SMC_DATA[14], AD19 GPIO5_C[3]/EBC_SDDO[3]/SMC_DATA[3], AD20 GPIO0_B[0]/EBC_SDCE0/SMC_ADDR[0]/HOST_DATA[0], AD21 GPIO0_B[2]/EBC_SDCE2/SMC_ADDR[2]/HOST_DATA[2], AD22 GPIO0_B[4]/EBC_BORDER1/SMC_WEN, AD23 GPIO0_C[1]/EBC_GDRL/SMC_DATA[9], AD24 GPIO0_C[7]/EBC_SDCE5/SMC_DATA[15], B13 GPIO3_A[7]/SMC_ADDR[15]/HOST_DATA[15], B14 GPIO3_C[6]/SMC_ADDR[16]/HOST_DATA[16], B15 GPIO3_C[5]/SMC_ADDR[12]/HOST_DATA[12], D16 GPIO3_C[7]/SMC_ADDR[17]/HOST_DATA[17], D17 GPIO3_D[2]/HOST_CSN, D19 GPIO3_D[4]/HOST_WRN, E16 GPIO3_C[3]/SMC_ADDR[10]/HOST_DATA[10], E17 GPIO3_D[7]/SMC_ADDR[9]/HOST_DATA[9], E18 GPIO3_D[3]/HOST_RDN, F14 GPIO3_D[0]/SMC_ADDR[18]/HOST_ADDR0, F17 GPIO3_A[6]/SMC_ADDR[14]/HOST_DATA[14], R19 GPIO3_D[6]/SMC_ADDR[8]/HOST_DATA[8], W17 GPIO1_A[1]/SMC_CSN0, W18 GPIO5_C[4]/EBC_SDDO[4]/SMC_DATA[4], W19 GPIO5_D[1]/EBC_SDCLK/SMC_ADDR[6]/HOST_DATA[6], Y17 GPIO0_B[5]/EBC_VCOM/SMC_BLSN0, Y18 GPIO5_C[0]/EBC_SDDO[0]/SMC_DATA[0], Y19 GPIO5_D[0]/EBC_SDLE/SMC_ADDR[5]/HOST_DATA[5], Y20 GPIO0_C[4]/EBC_GDPWR2/SMC_DATA[12], Y21 GPIO1_A[2]/SMC_CSN1, Y22 GPIO3_D[5]/SMC_ADDR[7]/HOST_DATA[7]
part D pins: B11 GPIO4_A[6]/HOST20_DRV_VBUS, G1 XOUT24M, G2 XIN24M, G17 GPIO4_A[5]/OTG_DRV_VBUS, H1 XOUT27M, H2 XIN27M, K6 NPOR, P22 RTCINT_OUT, P23 XOUT32K, P24 XIN32K, R23 HOST11_DM, R24 HOST11_DP, T20 HOST20_ID, T23 HOST20_DM, T24 HOST20_DP, U22 HOST20_VBUS, U24 HOST20_RKELVIN, V20 OTG_ID, V23 OTG_DM, V24 OTG_DP, W22 OTG_VBUS, W24 OTG_RKELVIN
part E pins: A9 GPIO1_A[5]/EMMC_PWR_EN/PWM3, D23 GPIO3_B[7]/EMMC_DATA5, E22 GPIO3_B[0]/EMMC_CLKOUT, F21 GPIO3_C[0]/EMMC_DATA6, F22 GPIO3_B[2]/EMMC_DATA0, F23 GPIO3_B[4]/EMMC_DATA2, F24 GPIO3_B[5]/EMMC_DATA3, G21 GPIO3_C[1]/EMMC_DATA7, G23 GPIO3_B[6]/EMMC_DATA4, H21 GPIO3_B[1]/EMMC_CMD, H24 GPIO3_B[3]/EMMC_DATA1, J19 GPIO0_D[6]/FLASH_CSN5, J20 GPIO1_A[0]/FLASH_CSN7/MDDR_TQ, J21 GPIO0_A[5]/FLASH_DQS, J22 GPIO0_D[5]/FLASH_CSN4, J23 GPIO4_B[2]/FLASH_DATA[10], J24 GPIO4_B[3]/FLASH_DATA[11], K19 FLASH_WP, K20 FLASH_WRN, K21 GPIO4_B[6]/FLASH_DATA[14], K22 GPIO0_D[3]/FLASH_CSN2, K23 GPIO0_D[4]/FLASH_CSN3, K24 GPIO0_D[2]/FLASH_CSN1, L19 FLASH_DATA[6], L20 GPIO4_B[0]/FLASH_DATA[8], L21 FLASH_DATA[7], L22 FLASH_DATA[2], L23 FLASH_DATA[3], L24 GPIO0_D[7]/FLASH_CSN6, M19 GPIO4_B[7]/FLASH_DATA[15], M20 GPIO4_B[5]/FLASH_DATA[13], M21 FLASH_CLE, M22 GPIO4_B[1]/FLASH_DATA[9], M23 FLASH_DATA[5], M24 FLASH_CSN0, N19 FLASH_DATA[1], N20 FLASH_RDY, N21 FLASH_RDN, N22 GPIO4_B[4]/FLASH_DATA[12], N23 FLASH_DATA[0], N24 FLASH_DATA[4], P19 FLASH_ALE
part F pins: A6 GPIO5_D[6]/SDMMC1_PWR_EN, A7 GPIO5_D[5]/SDMMC0_PWR_EN, B10 GPIO2_A[2]/SDMMC0_DETECT_N, B24 GPIO1_D[4]/SDMMC0_DATA2, C22 GPIO2_A[0]/SDMMC0_DATA6, C23 GPIO1_D[6]/SDMMC0_DATA4, D20 GPIO1_D[2]/SDMMC0_DATA0, D22 GPIO1_D[0]/SDMMC0_CLKOUT, D24 GPIO1_C[2]/SDMMC1_CMD, E20 GPIO1_D[7]/SDMMC0_DATA5, E23 GPIO2_A[1]/SDMMC0_DATA7, G19 GPIO1_D[5]/SDMMC0_DATA3, G20 GPIO1_D[1]/SDMMC0_CMD, G22 GPIO1_D[3]/SDMMC0_DATA1, G24 GPIO1_C[7]/SDMMC1_CLKOUT, H18 GPIO1_C[5]/SDMMC1_DATA2, H19 GPIO1_C[6]/SDMMC1_DATA3, H22 GPIO1_C[3]/SDMMC1_DATA0, H23 GPIO1_C[4]/SDMMC1_DATA1
part G pins: A18 GPIO4_C[5]/RMII_CRS_DVALID/MII_RXD_VALID, A20 GPIO4_C[0]/RMII_CLKOUT/RMII_CLKIN, A22 GPIO4_C[1]/RMII_TX_EN/MII_TX_EN, B18 GPIO5_A[3]/MII_TX_CLKIN, B23 GPIO4_C[6]/RMII_RXD1/MII_RXD1, C18 GPIO4_C[4]/RMII_RX_ERR/MII_RX_ERR, C19 GPIO4_C[2]/RMII_TXD1/MII_TXD1, D11 GPIO0_A[7]/MII_MDCLK, D18 GPIO0_A[6]/MII_MD, D21 GPIO4_C[3]/RMII_TXD0/MII_TXD0, E19 GPIO4_C[7]/RMII_RXD0/MII_RXD0, K5 TRST_N, L5 TCK, L6 TDI, M6 TMS, M7 TDO
part H pins: A17 GPIO5_B[3]/HSADC_DATA6, A19 GPIO5_A[7]/HSADC_DATA2, B17 GPIO5_B[2]/HSADC_DATA5, B19 GPIO5_B[5]/HSADC_DATA8/TS_VALID, B20 GPIO5_A[5]/HSADC_DATA0, C13 GPIO5_B[6]/HSADC_DATA9/TS_FAIL, C16 GPIO5_A[4]/TS_SYNC, C17 GPIO5_B[4]/HSADC_DATA7, C20 GPIO5_B[1]/HSADC_DATA4, E21 GPIO5_B[0]/HSADC_DATA3, F18 GPIO5_A[6]/HSADC_DATA1, F19 GPIO5_B[7]/HSADC_CLKOUT/GPS_CLK
part I pins: A3 GPIO1_C[0]/UART0_CTS_N/SDMMC1_DETECT_N, A4 GPIO3_A[5]/I2S1_LRCK_TX, A5 GPIO3_A[4]/I2S1_SDO, A8 GPIO2_B[2]/UART3_SIN, A10 GPIO1_A[4]/EMMC_WRITE_PRT/SPI0_CSN1, A12 GPIO1_A[6]/I2C1_SDA, A13 GPIO2_C[5]/SPI1_CSN0, A21 GPIO2_D[2]/I2S0_LRCK_RX/MII_TX_ERR, A23 GPIO2_D[5]/I2S0_SDO1/MII_RXD3, A24 GPIO2_D[6]/I2S0_SDO2/MII_TXD2, B4 GPIO2_A[7]/UART2_RTS_N, B5 GPIO3_A[3]/I2S1_SDI, B6 GPIO3_A[1]/I2S1_SCLK, B8 GPIO5_D[3]/I2C2_SDA, B12 GPIO1_A[7]/I2C1_SCL, B16 GPIO2_C[6]/SPI1_TXD, B21 GPIO4_D[7]/I2S0_LRCK_TX1, B22 GPIO2_D[3]/I2S0_SDI/MII_COL, C4 GPIO1_C[1]/UART0_RTS_N/SDMMC1_WRITE_PRT, C5 GPIO2_A[6]/UART2_CTS_N, C6 GPIO3_A[2]/I2S1_LRCK_RX, C7 GPIO2_A[4]/UART1_SIN, C9 GPIO2_B[6]/I2C0_SDA, C14 GPIO2_C[7]/SPI1_RXD, C15 GPIO4_A[7]/SPDIF_TX, C21 GPIO2_D[4]/I2S0_SDO0/MII_RXD2, C24 GPIO2_D[7]/I2S0_SDO3/MII_TXD3, D5 GPIO1_B[7]/UART0_SOUT, D6 GPIO2_B[4]/UART3_CTS_N/I2C3_SDA, D7 GPIO3_A[0]/I2S1_CLK, D8 GPIO1_B[6]/UART0_SIN, D9 GPIO5_D[4]/I2C2_SCL, D10 GPIO2_B[7]/I2C0_SCL, D14 GPIO2_C[0]/SPI0_CLK, D15 GPIO2_C[3]/SPI0_RXD, E6 GPIO2_B[0]/UART2_SIN, E7 GPIO2_B[5]/UART3_RTS_N/I2C3_SCL, E8 GPIO2_B[1]/UART2_SOUT, E9 GPIO2_A[5]/UART1_SOUT, E14 GPIO2_C[1]/SPI0_CSN0, E15 GPIO2_C[2]/SPI0_TXD, E24 GPIO2_D[0]/I2S0_CLK/MII_RX_CLKIN, F8 GPIO2_B[3]/UART3_SOUT, F15 GPIO1_A[3]/EMMC_DETECT_N/SPI1_CSN1, F16 GPIO2_C[4]/SPI1_CLK, F20 GPIO4_D[6]/I2S0_LRCK_TX0, H20 GPIO2_D[1]/I2S0_SCLK/MII_CRS
part J pins: A1 GPIO6_A[0], A2 GPIO6_B[7], A11 GPIO6_C[2], AA23 SARADC_AIN[0], AA24 SARADC_AIN[3], B1 GPIO6_B[6], B2 GPIO6_B[5], B3 GPIO6_A[1], B7 GPIO5_D[2]/PWM1/UART1_SIR_IN, B9 GPIO2_A[3]/SDMMC0_WRITE_PRT/PWM2/UART1_SIR_OUT, C1 GPIO6_A[5], C2 GPIO6_B[4], C3 GPIO6_A[2], C8 GPIO1_B[5]/PWM0, C10 GPIO4_D[4], C11 GPIO6_C[6], C12 GPIO6_C[0], D1 GPIO6_A[6], D2 GPIO6_A[7], D3 GPIO6_B[3], D4 GPIO6_A[3], D12 GPIO4_D[0], D13 GPIO6_C[3], E1 GPIO6_B[0], E2 GPIO5_A[0], E3 GPIO6_B[2], E4 GPIO5_A[2], E5 GPIO6_A[4], E10 GPIO6_C[5], E11 GPIO4_D[1], E12 GPIO6_C[1], E13 GPIO6_C[7], F1 GPIO6_B[1], F2 GPIO0_A[1], F3 GPIO5_A[1], F4 GPIO0_A[0], F9 GPIO4_D[3], F10 GPIO4_D[2], F11 GPIO4_D[5], F12 GPIO5_D[7], F13 GPIO6_C[4], G3 GPIO0_A[2], G4 GPIO0_A[4], H3 GPIO0_A[3], H4 GPIO4_A[3], J1 GPIO4_A[0], J2 GPIO4_A[1], J3 GPIO4_A[2], J4 GPIO4_A[4], N6 BTMODE, P7 EWAKEUP_STOP, P20 VDDCORE_EFUSE, R20 EFUSE_VQPS, T7 EWAKEUP_POWER, T19 VDDIO_EFUSE, V7 TEST, V8 GPIO6_D[2], V9 GPIO6_D[0], W7 GPIO6_D[3], W8 GPIO6_D[1], Y23 SARADC_AIN[1], Y24 SARADC_AIN[2]
part K pins: AB24 VDDA_SARADC, F5 AVDD_DPLL, F6 AHVDD_APLL, F7 AHVSS_APLL, G5 DVDD_APLL, G6 AVSS_DPLL, G7 DVSS_APLL, G8 VDDIO_AP1, G9 VDDIO_AP0, G10 VDDCORE, G11 VDDIO6, G12 VDDCORE, G13 VDDIO5, G14 VDDCORE, G15 VDDIO4, G16 VDDCORE, G18 VDDIO3, H5 DVDD_DPLL, H6 DVSS_DPLL, H7 DVSS_CGPLL, J5 AVDD_CGPLL, J6 DVDD_CGPLL, J7 AVSS_CGPLL, J18 VDDCORE, K7 VDDIO0, K10 GND, K11 GND, K12 GND, K13 GND, K14 GND, K15 GND, K18 VDDIO2, L7 VDDCORE, L10 GND, L11 GND, L12 GND, L13 GND, L14 GND, L15 GND, L18 VDDCORE, M5 VSSIO_DDR0, M10 GND, M11 GND, M12 GND, M13 GND, M14 GND, M15 GND, M18 VDDIO_FLASH1, N5 VDDIO_DDR0, N7 VDDCORE, N10 GND, N11 GND, N12 GND, N13 GND, N14 GND, N15 GND, N18 VDDCORE, P5 VSSIO_DDR1, P10 GND, P11 GND, P12 GND, P13 GND, P14 GND, P15 GND, P18 VDDIO_FLASH0, P21 VDDIO_RTC, R5 VDDIO_DDR1, R7 VDDCORE, R10 GND, R11 GND, R12 GND, R13 GND, R14 GND, R15 GND, R18 VDDCORE, R21 VSSIO_UHOST11, R22 VDDIO_UHOST11, T5 VSSIO_DDR2, T18 VDDIO1, T21 HOST20_VSSA, T22 HOST_VDD25, U5 VDDIO_DDR2, U7 VDDCORE, U18 VDDCORE_RTC, U19 HOST20_DVDD, U20 HOST20_VSSAC, U21 HOST20_DVSS, U23 HOST20_VDD33, V5 VSSIO_DDR3, V10 VDDCORE, V11 VDDIO_LCD0, V12 VDDCORE, V13 VDDIO_LCD1, V14 VDDCORE, V15 VDDIO_VIP, V16 VDDCORE, V17 VDDIO_SMC0, V18 VDDIO_SMC1, V19 OTG_DVDD, V21 OTG_VSSA, V22 OTG_VDD25, W5 VDDIO_DDR3, W20 OTG_VSSAC, W21 OTG_DVSS, W23 OTG_VDD33, Y5 VSSIO_DDR4, Y6 VDDIO_DDR4, Y7 VSSIO_DDR5, Y8 VDDIO_DDR5, Y9 VSSIO_DDR6, Y10 VDDIO_DDR6
part L pins: AA1 WE_B, AA2 CAS_B, AA3 ODT1, AA4 NC3, AA5 DLL_TEST_PIN[0], AA6 DQ12, AA7 DQ13, AA8 NC4, AA9 DQ28, AA10 DQ27, AB1 A10, AB2 RAS_B, AB3 NC2, AB4 A14, AB5 DQ9, AB6 DQ10, AB7 DM3, AB8 NC5, AB9 DQ26, AB10 DQ30, AC1 A8, AC2 A13, AC3 A7, AC4 DQ8, AC5 DM1, AC6 DQS1#, AC7 DQ14, AC8 DQ24, AC9 DQS3#, AC10 DQ29, AD1 A11, AD2 A15, AD3 A9, AD4 A12, AD5 DQ11, AD6 DQS1, AD7 DQ15, AD8 DQ25, AD9 DQS3, AD10 DQ31, K1 DQ3, K2 DQ2, K3 DQ1, K4 DQ0, L1 DQS0, L2 DQS0#, L3 DQ5, L4 DQ4, M1 DQ7, M2 DQ6, M3 DQ17, M4 DM0, N1 DQ19, N2 DQ18, N3 DM2, N4 DQ16, P1 DQS2, P2 DQS2#, P3 DQ21, P4 DQ20, P6 VREF0, R1 DQ23, R2 DQ22, R3 BA0, R4 ZQ_PIN, T1 A1, T2 A0, T3 BA1, T4 BA2, T6 ANALOG_TEST_PIN, U1 A2, U2 A3, U3 NC0, U4 NC1, U6 VREF1, V1 A6, V2 CS_B0, V3 A4, V4 A5, V6 RESET, W1 CS_B1, W2 ODT0, W3 CKE1, W4 RET_EN, W6 VREF2, W9 NC6, Y1 CK, Y2 CK#, Y3 CKE0, Y4 DLL_TEST_PIN[1]



